VERSION 5.8 ;
BUSBITCHARS "[]" ;
DIVIDERCHAR "/" ;
UNITS
    DATABASE MICRONS 1000 ;
END UNITS

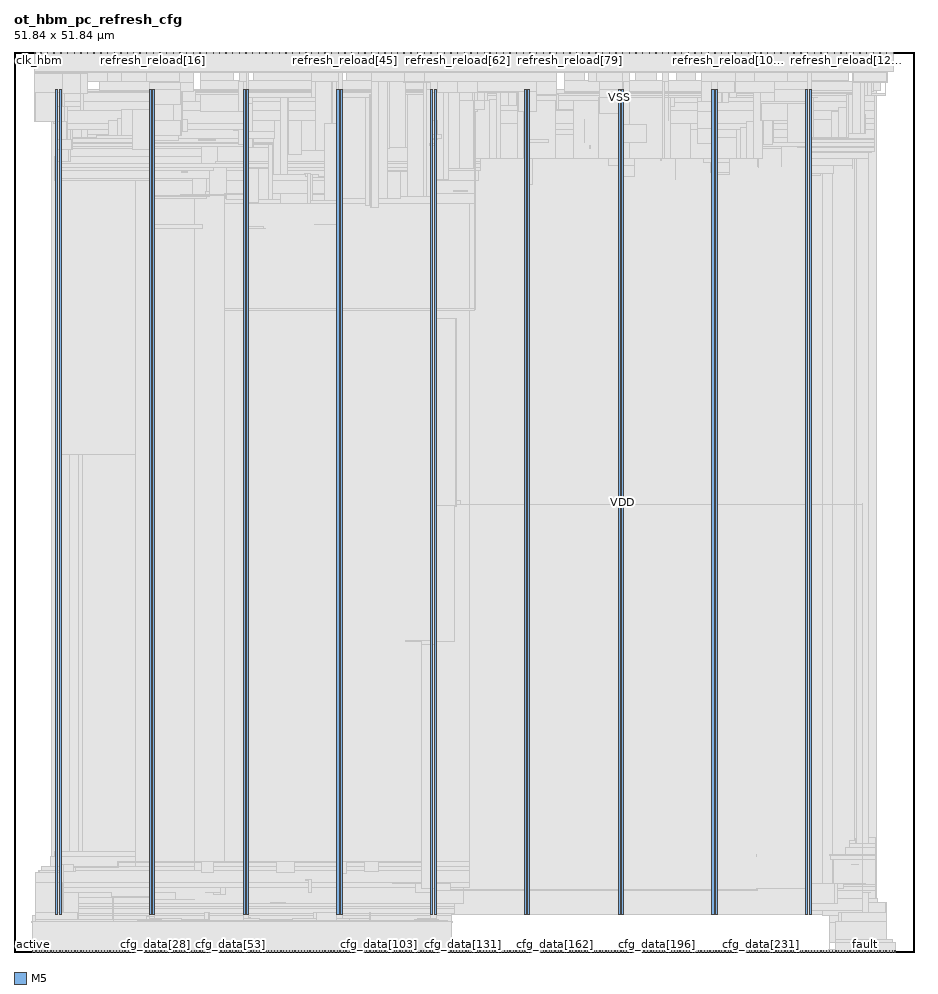
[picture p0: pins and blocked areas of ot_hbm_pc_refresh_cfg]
MACRO ot_hbm_pc_refresh_cfg
  FOREIGN ot_hbm_pc_refresh_cfg 0 0 ;
  CLASS BLOCK ;
  SIZE 51.84 BY 51.84 ;
  PIN active
    DIRECTION OUTPUT ;
    USE SIGNAL ;
    PORT
      LAYER M5 ;
        RECT  1.056 0 1.08 0.084 ;
    END
  END active
  PIN cfg_addr[0]
    DIRECTION INPUT ;
    USE SIGNAL ;
    PORT
      LAYER M5 ;
        RECT  1.248 0 1.272 0.084 ;
    END
  END cfg_addr[0]
  PIN cfg_addr[10]
    DIRECTION INPUT ;
    USE SIGNAL ;
    PORT
      LAYER M5 ;
        RECT  2.976 0 3 0.084 ;
    END
  END cfg_addr[10]
  PIN cfg_addr[11]
    DIRECTION INPUT ;
    USE SIGNAL ;
    PORT
      LAYER M5 ;
        RECT  3.12 0 3.144 0.084 ;
    END
  END cfg_addr[11]
  PIN cfg_addr[1]
    DIRECTION INPUT ;
    USE SIGNAL ;
    PORT
      LAYER M5 ;
        RECT  1.44 0 1.464 0.084 ;
    END
  END cfg_addr[1]
  PIN cfg_addr[2]
    DIRECTION INPUT ;
    USE SIGNAL ;
    PORT
      LAYER M5 ;
        RECT  1.584 0 1.608 0.084 ;
    END
  END cfg_addr[2]
  PIN cfg_addr[3]
    DIRECTION INPUT ;
    USE SIGNAL ;
    PORT
      LAYER M5 ;
        RECT  1.776 0 1.8 0.084 ;
    END
  END cfg_addr[3]
  PIN cfg_addr[4]
    DIRECTION INPUT ;
    USE SIGNAL ;
    PORT
      LAYER M5 ;
        RECT  1.92 0 1.944 0.084 ;
    END
  END cfg_addr[4]
  PIN cfg_addr[5]
    DIRECTION INPUT ;
    USE SIGNAL ;
    PORT
      LAYER M5 ;
        RECT  2.112 0 2.136 0.084 ;
    END
  END cfg_addr[5]
  PIN cfg_addr[6]
    DIRECTION INPUT ;
    USE SIGNAL ;
    PORT
      LAYER M5 ;
        RECT  2.256 0 2.28 0.084 ;
    END
  END cfg_addr[6]
  PIN cfg_addr[7]
    DIRECTION INPUT ;
    USE SIGNAL ;
    PORT
      LAYER M5 ;
        RECT  2.448 0 2.472 0.084 ;
    END
  END cfg_addr[7]
  PIN cfg_addr[8]
    DIRECTION INPUT ;
    USE SIGNAL ;
    PORT
      LAYER M5 ;
        RECT  2.64 0 2.664 0.084 ;
    END
  END cfg_addr[8]
  PIN cfg_addr[9]
    DIRECTION INPUT ;
    USE SIGNAL ;
    PORT
      LAYER M5 ;
        RECT  2.784 0 2.808 0.084 ;
    END
  END cfg_addr[9]
  PIN cfg_data[0]
    DIRECTION INPUT ;
    USE SIGNAL ;
    PORT
      LAYER M5 ;
        RECT  3.312 0 3.336 0.084 ;
    END
  END cfg_data[0]
  PIN cfg_data[100]
    DIRECTION INPUT ;
    USE SIGNAL ;
    PORT
      LAYER M5 ;
        RECT  20.496 0 20.52 0.084 ;
    END
  END cfg_data[100]
  PIN cfg_data[101]
    DIRECTION INPUT ;
    USE SIGNAL ;
    PORT
      LAYER M5 ;
        RECT  20.688 0 20.712 0.084 ;
    END
  END cfg_data[101]
  PIN cfg_data[102]
    DIRECTION INPUT ;
    USE SIGNAL ;
    PORT
      LAYER M5 ;
        RECT  20.832 0 20.856 0.084 ;
    END
  END cfg_data[102]
  PIN cfg_data[103]
    DIRECTION INPUT ;
    USE SIGNAL ;
    PORT
      LAYER M5 ;
        RECT  21.024 0 21.048 0.084 ;
    END
  END cfg_data[103]
  PIN cfg_data[104]
    DIRECTION INPUT ;
    USE SIGNAL ;
    PORT
      LAYER M5 ;
        RECT  21.168 0 21.192 0.084 ;
    END
  END cfg_data[104]
  PIN cfg_data[105]
    DIRECTION INPUT ;
    USE SIGNAL ;
    PORT
      LAYER M5 ;
        RECT  21.36 0 21.384 0.084 ;
    END
  END cfg_data[105]
  PIN cfg_data[106]
    DIRECTION INPUT ;
    USE SIGNAL ;
    PORT
      LAYER M5 ;
        RECT  21.504 0 21.528 0.084 ;
    END
  END cfg_data[106]
  PIN cfg_data[107]
    DIRECTION INPUT ;
    USE SIGNAL ;
    PORT
      LAYER M5 ;
        RECT  21.696 0 21.72 0.084 ;
    END
  END cfg_data[107]
  PIN cfg_data[108]
    DIRECTION INPUT ;
    USE SIGNAL ;
    PORT
      LAYER M5 ;
        RECT  21.888 0 21.912 0.084 ;
    END
  END cfg_data[108]
  PIN cfg_data[109]
    DIRECTION INPUT ;
    USE SIGNAL ;
    PORT
      LAYER M5 ;
        RECT  22.032 0 22.056 0.084 ;
    END
  END cfg_data[109]
  PIN cfg_data[10]
    DIRECTION INPUT ;
    USE SIGNAL ;
    PORT
      LAYER M5 ;
        RECT  5.04 0 5.064 0.084 ;
    END
  END cfg_data[10]
  PIN cfg_data[110]
    DIRECTION INPUT ;
    USE SIGNAL ;
    PORT
      LAYER M5 ;
        RECT  22.224 0 22.248 0.084 ;
    END
  END cfg_data[110]
  PIN cfg_data[111]
    DIRECTION INPUT ;
    USE SIGNAL ;
    PORT
      LAYER M5 ;
        RECT  22.368 0 22.392 0.084 ;
    END
  END cfg_data[111]
  PIN cfg_data[112]
    DIRECTION INPUT ;
    USE SIGNAL ;
    PORT
      LAYER M5 ;
        RECT  22.56 0 22.584 0.084 ;
    END
  END cfg_data[112]
  PIN cfg_data[113]
    DIRECTION INPUT ;
    USE SIGNAL ;
    PORT
      LAYER M5 ;
        RECT  22.752 0 22.776 0.084 ;
    END
  END cfg_data[113]
  PIN cfg_data[114]
    DIRECTION INPUT ;
    USE SIGNAL ;
    PORT
      LAYER M5 ;
        RECT  22.896 0 22.92 0.084 ;
    END
  END cfg_data[114]
  PIN cfg_data[115]
    DIRECTION INPUT ;
    USE SIGNAL ;
    PORT
      LAYER M5 ;
        RECT  23.088 0 23.112 0.084 ;
    END
  END cfg_data[115]
  PIN cfg_data[116]
    DIRECTION INPUT ;
    USE SIGNAL ;
    PORT
      LAYER M5 ;
        RECT  23.232 0 23.256 0.084 ;
    END
  END cfg_data[116]
  PIN cfg_data[117]
    DIRECTION INPUT ;
    USE SIGNAL ;
    PORT
      LAYER M5 ;
        RECT  23.424 0 23.448 0.084 ;
    END
  END cfg_data[117]
  PIN cfg_data[118]
    DIRECTION INPUT ;
    USE SIGNAL ;
    PORT
      LAYER M5 ;
        RECT  23.568 0 23.592 0.084 ;
    END
  END cfg_data[118]
  PIN cfg_data[119]
    DIRECTION INPUT ;
    USE SIGNAL ;
    PORT
      LAYER M5 ;
        RECT  23.76 0 23.784 0.084 ;
    END
  END cfg_data[119]
  PIN cfg_data[11]
    DIRECTION INPUT ;
    USE SIGNAL ;
    PORT
      LAYER M5 ;
        RECT  5.184 0 5.208 0.084 ;
    END
  END cfg_data[11]
  PIN cfg_data[120]
    DIRECTION INPUT ;
    USE SIGNAL ;
    PORT
      LAYER M5 ;
        RECT  23.952 0 23.976 0.084 ;
    END
  END cfg_data[120]
  PIN cfg_data[121]
    DIRECTION INPUT ;
    USE SIGNAL ;
    PORT
      LAYER M5 ;
        RECT  24.096 0 24.12 0.084 ;
    END
  END cfg_data[121]
  PIN cfg_data[122]
    DIRECTION INPUT ;
    USE SIGNAL ;
    PORT
      LAYER M5 ;
        RECT  24.288 0 24.312 0.084 ;
    END
  END cfg_data[122]
  PIN cfg_data[123]
    DIRECTION INPUT ;
    USE SIGNAL ;
    PORT
      LAYER M5 ;
        RECT  24.432 0 24.456 0.084 ;
    END
  END cfg_data[123]
  PIN cfg_data[124]
    DIRECTION INPUT ;
    USE SIGNAL ;
    PORT
      LAYER M5 ;
        RECT  24.624 0 24.648 0.084 ;
    END
  END cfg_data[124]
  PIN cfg_data[125]
    DIRECTION INPUT ;
    USE SIGNAL ;
    PORT
      LAYER M5 ;
        RECT  24.768 0 24.792 0.084 ;
    END
  END cfg_data[125]
  PIN cfg_data[126]
    DIRECTION INPUT ;
    USE SIGNAL ;
    PORT
      LAYER M5 ;
        RECT  24.96 0 24.984 0.084 ;
    END
  END cfg_data[126]
  PIN cfg_data[127]
    DIRECTION INPUT ;
    USE SIGNAL ;
    PORT
      LAYER M5 ;
        RECT  25.152 0 25.176 0.084 ;
    END
  END cfg_data[127]
  PIN cfg_data[128]
    DIRECTION INPUT ;
    USE SIGNAL ;
    PORT
      LAYER M5 ;
        RECT  25.296 0 25.32 0.084 ;
    END
  END cfg_data[128]
  PIN cfg_data[129]
    DIRECTION INPUT ;
    USE SIGNAL ;
    PORT
      LAYER M5 ;
        RECT  25.488 0 25.512 0.084 ;
    END
  END cfg_data[129]
  PIN cfg_data[12]
    DIRECTION INPUT ;
    USE SIGNAL ;
    PORT
      LAYER M5 ;
        RECT  5.376 0 5.4 0.084 ;
    END
  END cfg_data[12]
  PIN cfg_data[130]
    DIRECTION INPUT ;
    USE SIGNAL ;
    PORT
      LAYER M5 ;
        RECT  25.632 0 25.656 0.084 ;
    END
  END cfg_data[130]
  PIN cfg_data[131]
    DIRECTION INPUT ;
    USE SIGNAL ;
    PORT
      LAYER M5 ;
        RECT  25.824 0 25.848 0.084 ;
    END
  END cfg_data[131]
  PIN cfg_data[132]
    DIRECTION INPUT ;
    USE SIGNAL ;
    PORT
      LAYER M5 ;
        RECT  26.016 0 26.04 0.084 ;
    END
  END cfg_data[132]
  PIN cfg_data[133]
    DIRECTION INPUT ;
    USE SIGNAL ;
    PORT
      LAYER M5 ;
        RECT  26.16 0 26.184 0.084 ;
    END
  END cfg_data[133]
  PIN cfg_data[134]
    DIRECTION INPUT ;
    USE SIGNAL ;
    PORT
      LAYER M5 ;
        RECT  26.352 0 26.376 0.084 ;
    END
  END cfg_data[134]
  PIN cfg_data[135]
    DIRECTION INPUT ;
    USE SIGNAL ;
    PORT
      LAYER M5 ;
        RECT  26.496 0 26.52 0.084 ;
    END
  END cfg_data[135]
  PIN cfg_data[136]
    DIRECTION INPUT ;
    USE SIGNAL ;
    PORT
      LAYER M5 ;
        RECT  26.688 0 26.712 0.084 ;
    END
  END cfg_data[136]
  PIN cfg_data[137]
    DIRECTION INPUT ;
    USE SIGNAL ;
    PORT
      LAYER M5 ;
        RECT  26.832 0 26.856 0.084 ;
    END
  END cfg_data[137]
  PIN cfg_data[138]
    DIRECTION INPUT ;
    USE SIGNAL ;
    PORT
      LAYER M5 ;
        RECT  27.024 0 27.048 0.084 ;
    END
  END cfg_data[138]
  PIN cfg_data[139]
    DIRECTION INPUT ;
    USE SIGNAL ;
    PORT
      LAYER M5 ;
        RECT  27.216 0 27.24 0.084 ;
    END
  END cfg_data[139]
  PIN cfg_data[13]
    DIRECTION INPUT ;
    USE SIGNAL ;
    PORT
      LAYER M5 ;
        RECT  5.52 0 5.544 0.084 ;
    END
  END cfg_data[13]
  PIN cfg_data[140]
    DIRECTION INPUT ;
    USE SIGNAL ;
    PORT
      LAYER M5 ;
        RECT  27.36 0 27.384 0.084 ;
    END
  END cfg_data[140]
  PIN cfg_data[141]
    DIRECTION INPUT ;
    USE SIGNAL ;
    PORT
      LAYER M5 ;
        RECT  27.552 0 27.576 0.084 ;
    END
  END cfg_data[141]
  PIN cfg_data[142]
    DIRECTION INPUT ;
    USE SIGNAL ;
    PORT
      LAYER M5 ;
        RECT  27.696 0 27.72 0.084 ;
    END
  END cfg_data[142]
  PIN cfg_data[143]
    DIRECTION INPUT ;
    USE SIGNAL ;
    PORT
      LAYER M5 ;
        RECT  27.888 0 27.912 0.084 ;
    END
  END cfg_data[143]
  PIN cfg_data[144]
    DIRECTION INPUT ;
    USE SIGNAL ;
    PORT
      LAYER M5 ;
        RECT  28.08 0 28.104 0.084 ;
    END
  END cfg_data[144]
  PIN cfg_data[145]
    DIRECTION INPUT ;
    USE SIGNAL ;
    PORT
      LAYER M5 ;
        RECT  28.224 0 28.248 0.084 ;
    END
  END cfg_data[145]
  PIN cfg_data[146]
    DIRECTION INPUT ;
    USE SIGNAL ;
    PORT
      LAYER M5 ;
        RECT  28.416 0 28.44 0.084 ;
    END
  END cfg_data[146]
  PIN cfg_data[147]
    DIRECTION INPUT ;
    USE SIGNAL ;
    PORT
      LAYER M5 ;
        RECT  28.56 0 28.584 0.084 ;
    END
  END cfg_data[147]
  PIN cfg_data[148]
    DIRECTION INPUT ;
    USE SIGNAL ;
    PORT
      LAYER M5 ;
        RECT  28.752 0 28.776 0.084 ;
    END
  END cfg_data[148]
  PIN cfg_data[149]
    DIRECTION INPUT ;
    USE SIGNAL ;
    PORT
      LAYER M5 ;
        RECT  28.896 0 28.92 0.084 ;
    END
  END cfg_data[149]
  PIN cfg_data[14]
    DIRECTION INPUT ;
    USE SIGNAL ;
    PORT
      LAYER M5 ;
        RECT  5.712 0 5.736 0.084 ;
    END
  END cfg_data[14]
  PIN cfg_data[150]
    DIRECTION INPUT ;
    USE SIGNAL ;
    PORT
      LAYER M5 ;
        RECT  29.088 0 29.112 0.084 ;
    END
  END cfg_data[150]
  PIN cfg_data[151]
    DIRECTION INPUT ;
    USE SIGNAL ;
    PORT
      LAYER M5 ;
        RECT  29.28 0 29.304 0.084 ;
    END
  END cfg_data[151]
  PIN cfg_data[152]
    DIRECTION INPUT ;
    USE SIGNAL ;
    PORT
      LAYER M5 ;
        RECT  29.424 0 29.448 0.084 ;
    END
  END cfg_data[152]
  PIN cfg_data[153]
    DIRECTION INPUT ;
    USE SIGNAL ;
    PORT
      LAYER M5 ;
        RECT  29.616 0 29.64 0.084 ;
    END
  END cfg_data[153]
  PIN cfg_data[154]
    DIRECTION INPUT ;
    USE SIGNAL ;
    PORT
      LAYER M5 ;
        RECT  29.76 0 29.784 0.084 ;
    END
  END cfg_data[154]
  PIN cfg_data[155]
    DIRECTION INPUT ;
    USE SIGNAL ;
    PORT
      LAYER M5 ;
        RECT  29.952 0 29.976 0.084 ;
    END
  END cfg_data[155]
  PIN cfg_data[156]
    DIRECTION INPUT ;
    USE SIGNAL ;
    PORT
      LAYER M5 ;
        RECT  30.096 0 30.12 0.084 ;
    END
  END cfg_data[156]
  PIN cfg_data[157]
    DIRECTION INPUT ;
    USE SIGNAL ;
    PORT
      LAYER M5 ;
        RECT  30.288 0 30.312 0.084 ;
    END
  END cfg_data[157]
  PIN cfg_data[158]
    DIRECTION INPUT ;
    USE SIGNAL ;
    PORT
      LAYER M5 ;
        RECT  30.48 0 30.504 0.084 ;
    END
  END cfg_data[158]
  PIN cfg_data[159]
    DIRECTION INPUT ;
    USE SIGNAL ;
    PORT
      LAYER M5 ;
        RECT  30.624 0 30.648 0.084 ;
    END
  END cfg_data[159]
  PIN cfg_data[15]
    DIRECTION INPUT ;
    USE SIGNAL ;
    PORT
      LAYER M5 ;
        RECT  5.904 0 5.928 0.084 ;
    END
  END cfg_data[15]
  PIN cfg_data[160]
    DIRECTION INPUT ;
    USE SIGNAL ;
    PORT
      LAYER M5 ;
        RECT  30.816 0 30.84 0.084 ;
    END
  END cfg_data[160]
  PIN cfg_data[161]
    DIRECTION INPUT ;
    USE SIGNAL ;
    PORT
      LAYER M5 ;
        RECT  30.96 0 30.984 0.084 ;
    END
  END cfg_data[161]
  PIN cfg_data[162]
    DIRECTION INPUT ;
    USE SIGNAL ;
    PORT
      LAYER M5 ;
        RECT  31.152 0 31.176 0.084 ;
    END
  END cfg_data[162]
  PIN cfg_data[163]
    DIRECTION INPUT ;
    USE SIGNAL ;
    PORT
      LAYER M5 ;
        RECT  31.344 0 31.368 0.084 ;
    END
  END cfg_data[163]
  PIN cfg_data[164]
    DIRECTION INPUT ;
    USE SIGNAL ;
    PORT
      LAYER M5 ;
        RECT  31.488 0 31.512 0.084 ;
    END
  END cfg_data[164]
  PIN cfg_data[165]
    DIRECTION INPUT ;
    USE SIGNAL ;
    PORT
      LAYER M5 ;
        RECT  31.68 0 31.704 0.084 ;
    END
  END cfg_data[165]
  PIN cfg_data[166]
    DIRECTION INPUT ;
    USE SIGNAL ;
    PORT
      LAYER M5 ;
        RECT  31.824 0 31.848 0.084 ;
    END
  END cfg_data[166]
  PIN cfg_data[167]
    DIRECTION INPUT ;
    USE SIGNAL ;
    PORT
      LAYER M5 ;
        RECT  32.016 0 32.04 0.084 ;
    END
  END cfg_data[167]
  PIN cfg_data[168]
    DIRECTION INPUT ;
    USE SIGNAL ;
    PORT
      LAYER M5 ;
        RECT  32.16 0 32.184 0.084 ;
    END
  END cfg_data[168]
  PIN cfg_data[169]
    DIRECTION INPUT ;
    USE SIGNAL ;
    PORT
      LAYER M5 ;
        RECT  32.352 0 32.376 0.084 ;
    END
  END cfg_data[169]
  PIN cfg_data[16]
    DIRECTION INPUT ;
    USE SIGNAL ;
    PORT
      LAYER M5 ;
        RECT  6.048 0 6.072 0.084 ;
    END
  END cfg_data[16]
  PIN cfg_data[170]
    DIRECTION INPUT ;
    USE SIGNAL ;
    PORT
      LAYER M5 ;
        RECT  32.544 0 32.568 0.084 ;
    END
  END cfg_data[170]
  PIN cfg_data[171]
    DIRECTION INPUT ;
    USE SIGNAL ;
    PORT
      LAYER M5 ;
        RECT  32.688 0 32.712 0.084 ;
    END
  END cfg_data[171]
  PIN cfg_data[172]
    DIRECTION INPUT ;
    USE SIGNAL ;
    PORT
      LAYER M5 ;
        RECT  32.88 0 32.904 0.084 ;
    END
  END cfg_data[172]
  PIN cfg_data[173]
    DIRECTION INPUT ;
    USE SIGNAL ;
    PORT
      LAYER M5 ;
        RECT  33.024 0 33.048 0.084 ;
    END
  END cfg_data[173]
  PIN cfg_data[174]
    DIRECTION INPUT ;
    USE SIGNAL ;
    PORT
      LAYER M5 ;
        RECT  33.216 0 33.24 0.084 ;
    END
  END cfg_data[174]
  PIN cfg_data[175]
    DIRECTION INPUT ;
    USE SIGNAL ;
    PORT
      LAYER M5 ;
        RECT  33.408 0 33.432 0.084 ;
    END
  END cfg_data[175]
  PIN cfg_data[176]
    DIRECTION INPUT ;
    USE SIGNAL ;
    PORT
      LAYER M5 ;
        RECT  33.552 0 33.576 0.084 ;
    END
  END cfg_data[176]
  PIN cfg_data[177]
    DIRECTION INPUT ;
    USE SIGNAL ;
    PORT
      LAYER M5 ;
        RECT  33.744 0 33.768 0.084 ;
    END
  END cfg_data[177]
  PIN cfg_data[178]
    DIRECTION INPUT ;
    USE SIGNAL ;
    PORT
      LAYER M5 ;
        RECT  33.888 0 33.912 0.084 ;
    END
  END cfg_data[178]
  PIN cfg_data[179]
    DIRECTION INPUT ;
    USE SIGNAL ;
    PORT
      LAYER M5 ;
        RECT  34.08 0 34.104 0.084 ;
    END
  END cfg_data[179]
  PIN cfg_data[17]
    DIRECTION INPUT ;
    USE SIGNAL ;
    PORT
      LAYER M5 ;
        RECT  6.24 0 6.264 0.084 ;
    END
  END cfg_data[17]
  PIN cfg_data[180]
    DIRECTION INPUT ;
    USE SIGNAL ;
    PORT
      LAYER M5 ;
        RECT  34.224 0 34.248 0.084 ;
    END
  END cfg_data[180]
  PIN cfg_data[181]
    DIRECTION INPUT ;
    USE SIGNAL ;
    PORT
      LAYER M5 ;
        RECT  34.416 0 34.44 0.084 ;
    END
  END cfg_data[181]
  PIN cfg_data[182]
    DIRECTION INPUT ;
    USE SIGNAL ;
    PORT
      LAYER M5 ;
        RECT  34.608 0 34.632 0.084 ;
    END
  END cfg_data[182]
  PIN cfg_data[183]
    DIRECTION INPUT ;
    USE SIGNAL ;
    PORT
      LAYER M5 ;
        RECT  34.752 0 34.776 0.084 ;
    END
  END cfg_data[183]
  PIN cfg_data[184]
    DIRECTION INPUT ;
    USE SIGNAL ;
    PORT
      LAYER M5 ;
        RECT  34.944 0 34.968 0.084 ;
    END
  END cfg_data[184]
  PIN cfg_data[185]
    DIRECTION INPUT ;
    USE SIGNAL ;
    PORT
      LAYER M5 ;
        RECT  35.088 0 35.112 0.084 ;
    END
  END cfg_data[185]
  PIN cfg_data[186]
    DIRECTION INPUT ;
    USE SIGNAL ;
    PORT
      LAYER M5 ;
        RECT  35.28 0 35.304 0.084 ;
    END
  END cfg_data[186]
  PIN cfg_data[187]
    DIRECTION INPUT ;
    USE SIGNAL ;
    PORT
      LAYER M5 ;
        RECT  35.424 0 35.448 0.084 ;
    END
  END cfg_data[187]
  PIN cfg_data[188]
    DIRECTION INPUT ;
    USE SIGNAL ;
    PORT
      LAYER M5 ;
        RECT  35.616 0 35.64 0.084 ;
    END
  END cfg_data[188]
  PIN cfg_data[189]
    DIRECTION INPUT ;
    USE SIGNAL ;
    PORT
      LAYER M5 ;
        RECT  35.808 0 35.832 0.084 ;
    END
  END cfg_data[189]
  PIN cfg_data[18]
    DIRECTION INPUT ;
    USE SIGNAL ;
    PORT
      LAYER M5 ;
        RECT  6.384 0 6.408 0.084 ;
    END
  END cfg_data[18]
  PIN cfg_data[190]
    DIRECTION INPUT ;
    USE SIGNAL ;
    PORT
      LAYER M5 ;
        RECT  35.952 0 35.976 0.084 ;
    END
  END cfg_data[190]
  PIN cfg_data[191]
    DIRECTION INPUT ;
    USE SIGNAL ;
    PORT
      LAYER M5 ;
        RECT  36.144 0 36.168 0.084 ;
    END
  END cfg_data[191]
  PIN cfg_data[192]
    DIRECTION INPUT ;
    USE SIGNAL ;
    PORT
      LAYER M5 ;
        RECT  36.288 0 36.312 0.084 ;
    END
  END cfg_data[192]
  PIN cfg_data[193]
    DIRECTION INPUT ;
    USE SIGNAL ;
    PORT
      LAYER M5 ;
        RECT  36.48 0 36.504 0.084 ;
    END
  END cfg_data[193]
  PIN cfg_data[194]
    DIRECTION INPUT ;
    USE SIGNAL ;
    PORT
      LAYER M5 ;
        RECT  36.672 0 36.696 0.084 ;
    END
  END cfg_data[194]
  PIN cfg_data[195]
    DIRECTION INPUT ;
    USE SIGNAL ;
    PORT
      LAYER M5 ;
        RECT  36.816 0 36.84 0.084 ;
    END
  END cfg_data[195]
  PIN cfg_data[196]
    DIRECTION INPUT ;
    USE SIGNAL ;
    PORT
      LAYER M5 ;
        RECT  37.008 0 37.032 0.084 ;
    END
  END cfg_data[196]
  PIN cfg_data[197]
    DIRECTION INPUT ;
    USE SIGNAL ;
    PORT
      LAYER M5 ;
        RECT  37.152 0 37.176 0.084 ;
    END
  END cfg_data[197]
  PIN cfg_data[198]
    DIRECTION INPUT ;
    USE SIGNAL ;
    PORT
      LAYER M5 ;
        RECT  37.344 0 37.368 0.084 ;
    END
  END cfg_data[198]
  PIN cfg_data[199]
    DIRECTION INPUT ;
    USE SIGNAL ;
    PORT
      LAYER M5 ;
        RECT  37.488 0 37.512 0.084 ;
    END
  END cfg_data[199]
  PIN cfg_data[19]
    DIRECTION INPUT ;
    USE SIGNAL ;
    PORT
      LAYER M5 ;
        RECT  6.576 0 6.6 0.084 ;
    END
  END cfg_data[19]
  PIN cfg_data[1]
    DIRECTION INPUT ;
    USE SIGNAL ;
    PORT
      LAYER M5 ;
        RECT  3.504 0 3.528 0.084 ;
    END
  END cfg_data[1]
  PIN cfg_data[200]
    DIRECTION INPUT ;
    USE SIGNAL ;
    PORT
      LAYER M5 ;
        RECT  37.68 0 37.704 0.084 ;
    END
  END cfg_data[200]
  PIN cfg_data[201]
    DIRECTION INPUT ;
    USE SIGNAL ;
    PORT
      LAYER M5 ;
        RECT  37.872 0 37.896 0.084 ;
    END
  END cfg_data[201]
  PIN cfg_data[202]
    DIRECTION INPUT ;
    USE SIGNAL ;
    PORT
      LAYER M5 ;
        RECT  38.016 0 38.04 0.084 ;
    END
  END cfg_data[202]
  PIN cfg_data[203]
    DIRECTION INPUT ;
    USE SIGNAL ;
    PORT
      LAYER M5 ;
        RECT  38.208 0 38.232 0.084 ;
    END
  END cfg_data[203]
  PIN cfg_data[204]
    DIRECTION INPUT ;
    USE SIGNAL ;
    PORT
      LAYER M5 ;
        RECT  38.352 0 38.376 0.084 ;
    END
  END cfg_data[204]
  PIN cfg_data[205]
    DIRECTION INPUT ;
    USE SIGNAL ;
    PORT
      LAYER M5 ;
        RECT  38.544 0 38.568 0.084 ;
    END
  END cfg_data[205]
  PIN cfg_data[206]
    DIRECTION INPUT ;
    USE SIGNAL ;
    PORT
      LAYER M5 ;
        RECT  38.736 0 38.76 0.084 ;
    END
  END cfg_data[206]
  PIN cfg_data[207]
    DIRECTION INPUT ;
    USE SIGNAL ;
    PORT
      LAYER M5 ;
        RECT  38.88 0 38.904 0.084 ;
    END
  END cfg_data[207]
  PIN cfg_data[208]
    DIRECTION INPUT ;
    USE SIGNAL ;
    PORT
      LAYER M5 ;
        RECT  39.072 0 39.096 0.084 ;
    END
  END cfg_data[208]
  PIN cfg_data[209]
    DIRECTION INPUT ;
    USE SIGNAL ;
    PORT
      LAYER M5 ;
        RECT  39.216 0 39.24 0.084 ;
    END
  END cfg_data[209]
  PIN cfg_data[20]
    DIRECTION INPUT ;
    USE SIGNAL ;
    PORT
      LAYER M5 ;
        RECT  6.768 0 6.792 0.084 ;
    END
  END cfg_data[20]
  PIN cfg_data[210]
    DIRECTION INPUT ;
    USE SIGNAL ;
    PORT
      LAYER M5 ;
        RECT  39.408 0 39.432 0.084 ;
    END
  END cfg_data[210]
  PIN cfg_data[211]
    DIRECTION INPUT ;
    USE SIGNAL ;
    PORT
      LAYER M5 ;
        RECT  39.552 0 39.576 0.084 ;
    END
  END cfg_data[211]
  PIN cfg_data[212]
    DIRECTION INPUT ;
    USE SIGNAL ;
    PORT
      LAYER M5 ;
        RECT  39.744 0 39.768 0.084 ;
    END
  END cfg_data[212]
  PIN cfg_data[213]
    DIRECTION INPUT ;
    USE SIGNAL ;
    PORT
      LAYER M5 ;
        RECT  39.936 0 39.96 0.084 ;
    END
  END cfg_data[213]
  PIN cfg_data[214]
    DIRECTION INPUT ;
    USE SIGNAL ;
    PORT
      LAYER M5 ;
        RECT  40.08 0 40.104 0.084 ;
    END
  END cfg_data[214]
  PIN cfg_data[215]
    DIRECTION INPUT ;
    USE SIGNAL ;
    PORT
      LAYER M5 ;
        RECT  40.272 0 40.296 0.084 ;
    END
  END cfg_data[215]
  PIN cfg_data[216]
    DIRECTION INPUT ;
    USE SIGNAL ;
    PORT
      LAYER M5 ;
        RECT  40.416 0 40.44 0.084 ;
    END
  END cfg_data[216]
  PIN cfg_data[217]
    DIRECTION INPUT ;
    USE SIGNAL ;
    PORT
      LAYER M5 ;
        RECT  40.608 0 40.632 0.084 ;
    END
  END cfg_data[217]
  PIN cfg_data[218]
    DIRECTION INPUT ;
    USE SIGNAL ;
    PORT
      LAYER M5 ;
        RECT  40.752 0 40.776 0.084 ;
    END
  END cfg_data[218]
  PIN cfg_data[219]
    DIRECTION INPUT ;
    USE SIGNAL ;
    PORT
      LAYER M5 ;
        RECT  40.944 0 40.968 0.084 ;
    END
  END cfg_data[219]
  PIN cfg_data[21]
    DIRECTION INPUT ;
    USE SIGNAL ;
    PORT
      LAYER M5 ;
        RECT  6.912 0 6.936 0.084 ;
    END
  END cfg_data[21]
  PIN cfg_data[220]
    DIRECTION INPUT ;
    USE SIGNAL ;
    PORT
      LAYER M5 ;
        RECT  41.136 0 41.16 0.084 ;
    END
  END cfg_data[220]
  PIN cfg_data[221]
    DIRECTION INPUT ;
    USE SIGNAL ;
    PORT
      LAYER M5 ;
        RECT  41.28 0 41.304 0.084 ;
    END
  END cfg_data[221]
  PIN cfg_data[222]
    DIRECTION INPUT ;
    USE SIGNAL ;
    PORT
      LAYER M5 ;
        RECT  41.472 0 41.496 0.084 ;
    END
  END cfg_data[222]
  PIN cfg_data[223]
    DIRECTION INPUT ;
    USE SIGNAL ;
    PORT
      LAYER M5 ;
        RECT  41.616 0 41.64 0.084 ;
    END
  END cfg_data[223]
  PIN cfg_data[224]
    DIRECTION INPUT ;
    USE SIGNAL ;
    PORT
      LAYER M5 ;
        RECT  41.808 0 41.832 0.084 ;
    END
  END cfg_data[224]
  PIN cfg_data[225]
    DIRECTION INPUT ;
    USE SIGNAL ;
    PORT
      LAYER M5 ;
        RECT  42 0 42.024 0.084 ;
    END
  END cfg_data[225]
  PIN cfg_data[226]
    DIRECTION INPUT ;
    USE SIGNAL ;
    PORT
      LAYER M5 ;
        RECT  42.144 0 42.168 0.084 ;
    END
  END cfg_data[226]
  PIN cfg_data[227]
    DIRECTION INPUT ;
    USE SIGNAL ;
    PORT
      LAYER M5 ;
        RECT  42.336 0 42.36 0.084 ;
    END
  END cfg_data[227]
  PIN cfg_data[228]
    DIRECTION INPUT ;
    USE SIGNAL ;
    PORT
      LAYER M5 ;
        RECT  42.48 0 42.504 0.084 ;
    END
  END cfg_data[228]
  PIN cfg_data[229]
    DIRECTION INPUT ;
    USE SIGNAL ;
    PORT
      LAYER M5 ;
        RECT  42.672 0 42.696 0.084 ;
    END
  END cfg_data[229]
  PIN cfg_data[22]
    DIRECTION INPUT ;
    USE SIGNAL ;
    PORT
      LAYER M5 ;
        RECT  7.104 0 7.128 0.084 ;
    END
  END cfg_data[22]
  PIN cfg_data[230]
    DIRECTION INPUT ;
    USE SIGNAL ;
    PORT
      LAYER M5 ;
        RECT  42.816 0 42.84 0.084 ;
    END
  END cfg_data[230]
  PIN cfg_data[231]
    DIRECTION INPUT ;
    USE SIGNAL ;
    PORT
      LAYER M5 ;
        RECT  43.008 0 43.032 0.084 ;
    END
  END cfg_data[231]
  PIN cfg_data[232]
    DIRECTION INPUT ;
    USE SIGNAL ;
    PORT
      LAYER M5 ;
        RECT  43.2 0 43.224 0.084 ;
    END
  END cfg_data[232]
  PIN cfg_data[233]
    DIRECTION INPUT ;
    USE SIGNAL ;
    PORT
      LAYER M5 ;
        RECT  43.344 0 43.368 0.084 ;
    END
  END cfg_data[233]
  PIN cfg_data[234]
    DIRECTION INPUT ;
    USE SIGNAL ;
    PORT
      LAYER M5 ;
        RECT  43.536 0 43.56 0.084 ;
    END
  END cfg_data[234]
  PIN cfg_data[235]
    DIRECTION INPUT ;
    USE SIGNAL ;
    PORT
      LAYER M5 ;
        RECT  43.68 0 43.704 0.084 ;
    END
  END cfg_data[235]
  PIN cfg_data[236]
    DIRECTION INPUT ;
    USE SIGNAL ;
    PORT
      LAYER M5 ;
        RECT  43.872 0 43.896 0.084 ;
    END
  END cfg_data[236]
  PIN cfg_data[237]
    DIRECTION INPUT ;
    USE SIGNAL ;
    PORT
      LAYER M5 ;
        RECT  44.016 0 44.04 0.084 ;
    END
  END cfg_data[237]
  PIN cfg_data[238]
    DIRECTION INPUT ;
    USE SIGNAL ;
    PORT
      LAYER M5 ;
        RECT  44.208 0 44.232 0.084 ;
    END
  END cfg_data[238]
  PIN cfg_data[239]
    DIRECTION INPUT ;
    USE SIGNAL ;
    PORT
      LAYER M5 ;
        RECT  44.4 0 44.424 0.084 ;
    END
  END cfg_data[239]
  PIN cfg_data[23]
    DIRECTION INPUT ;
    USE SIGNAL ;
    PORT
      LAYER M5 ;
        RECT  7.248 0 7.272 0.084 ;
    END
  END cfg_data[23]
  PIN cfg_data[240]
    DIRECTION INPUT ;
    USE SIGNAL ;
    PORT
      LAYER M5 ;
        RECT  44.544 0 44.568 0.084 ;
    END
  END cfg_data[240]
  PIN cfg_data[241]
    DIRECTION INPUT ;
    USE SIGNAL ;
    PORT
      LAYER M5 ;
        RECT  44.736 0 44.76 0.084 ;
    END
  END cfg_data[241]
  PIN cfg_data[242]
    DIRECTION INPUT ;
    USE SIGNAL ;
    PORT
      LAYER M5 ;
        RECT  44.88 0 44.904 0.084 ;
    END
  END cfg_data[242]
  PIN cfg_data[243]
    DIRECTION INPUT ;
    USE SIGNAL ;
    PORT
      LAYER M5 ;
        RECT  45.072 0 45.096 0.084 ;
    END
  END cfg_data[243]
  PIN cfg_data[244]
    DIRECTION INPUT ;
    USE SIGNAL ;
    PORT
      LAYER M5 ;
        RECT  45.264 0 45.288 0.084 ;
    END
  END cfg_data[244]
  PIN cfg_data[245]
    DIRECTION INPUT ;
    USE SIGNAL ;
    PORT
      LAYER M5 ;
        RECT  45.408 0 45.432 0.084 ;
    END
  END cfg_data[245]
  PIN cfg_data[246]
    DIRECTION INPUT ;
    USE SIGNAL ;
    PORT
      LAYER M5 ;
        RECT  45.6 0 45.624 0.084 ;
    END
  END cfg_data[246]
  PIN cfg_data[247]
    DIRECTION INPUT ;
    USE SIGNAL ;
    PORT
      LAYER M5 ;
        RECT  45.744 0 45.768 0.084 ;
    END
  END cfg_data[247]
  PIN cfg_data[248]
    DIRECTION INPUT ;
    USE SIGNAL ;
    PORT
      LAYER M5 ;
        RECT  45.936 0 45.96 0.084 ;
    END
  END cfg_data[248]
  PIN cfg_data[249]
    DIRECTION INPUT ;
    USE SIGNAL ;
    PORT
      LAYER M5 ;
        RECT  46.08 0 46.104 0.084 ;
    END
  END cfg_data[249]
  PIN cfg_data[24]
    DIRECTION INPUT ;
    USE SIGNAL ;
    PORT
      LAYER M5 ;
        RECT  7.44 0 7.464 0.084 ;
    END
  END cfg_data[24]
  PIN cfg_data[250]
    DIRECTION INPUT ;
    USE SIGNAL ;
    PORT
      LAYER M5 ;
        RECT  46.272 0 46.296 0.084 ;
    END
  END cfg_data[250]
  PIN cfg_data[251]
    DIRECTION INPUT ;
    USE SIGNAL ;
    PORT
      LAYER M5 ;
        RECT  46.464 0 46.488 0.084 ;
    END
  END cfg_data[251]
  PIN cfg_data[252]
    DIRECTION INPUT ;
    USE SIGNAL ;
    PORT
      LAYER M5 ;
        RECT  46.608 0 46.632 0.084 ;
    END
  END cfg_data[252]
  PIN cfg_data[253]
    DIRECTION INPUT ;
    USE SIGNAL ;
    PORT
      LAYER M5 ;
        RECT  46.8 0 46.824 0.084 ;
    END
  END cfg_data[253]
  PIN cfg_data[254]
    DIRECTION INPUT ;
    USE SIGNAL ;
    PORT
      LAYER M5 ;
        RECT  46.944 0 46.968 0.084 ;
    END
  END cfg_data[254]
  PIN cfg_data[255]
    DIRECTION INPUT ;
    USE SIGNAL ;
    PORT
      LAYER M5 ;
        RECT  47.136 0 47.16 0.084 ;
    END
  END cfg_data[255]
  PIN cfg_data[25]
    DIRECTION INPUT ;
    USE SIGNAL ;
    PORT
      LAYER M5 ;
        RECT  7.584 0 7.608 0.084 ;
    END
  END cfg_data[25]
  PIN cfg_data[26]
    DIRECTION INPUT ;
    USE SIGNAL ;
    PORT
      LAYER M5 ;
        RECT  7.776 0 7.8 0.084 ;
    END
  END cfg_data[26]
  PIN cfg_data[27]
    DIRECTION INPUT ;
    USE SIGNAL ;
    PORT
      LAYER M5 ;
        RECT  7.968 0 7.992 0.084 ;
    END
  END cfg_data[27]
  PIN cfg_data[28]
    DIRECTION INPUT ;
    USE SIGNAL ;
    PORT
      LAYER M5 ;
        RECT  8.112 0 8.136 0.084 ;
    END
  END cfg_data[28]
  PIN cfg_data[29]
    DIRECTION INPUT ;
    USE SIGNAL ;
    PORT
      LAYER M5 ;
        RECT  8.304 0 8.328 0.084 ;
    END
  END cfg_data[29]
  PIN cfg_data[2]
    DIRECTION INPUT ;
    USE SIGNAL ;
    PORT
      LAYER M5 ;
        RECT  3.648 0 3.672 0.084 ;
    END
  END cfg_data[2]
  PIN cfg_data[30]
    DIRECTION INPUT ;
    USE SIGNAL ;
    PORT
      LAYER M5 ;
        RECT  8.448 0 8.472 0.084 ;
    END
  END cfg_data[30]
  PIN cfg_data[31]
    DIRECTION INPUT ;
    USE SIGNAL ;
    PORT
      LAYER M5 ;
        RECT  8.64 0 8.664 0.084 ;
    END
  END cfg_data[31]
  PIN cfg_data[32]
    DIRECTION INPUT ;
    USE SIGNAL ;
    PORT
      LAYER M5 ;
        RECT  8.832 0 8.856 0.084 ;
    END
  END cfg_data[32]
  PIN cfg_data[33]
    DIRECTION INPUT ;
    USE SIGNAL ;
    PORT
      LAYER M5 ;
        RECT  8.976 0 9 0.084 ;
    END
  END cfg_data[33]
  PIN cfg_data[34]
    DIRECTION INPUT ;
    USE SIGNAL ;
    PORT
      LAYER M5 ;
        RECT  9.168 0 9.192 0.084 ;
    END
  END cfg_data[34]
  PIN cfg_data[35]
    DIRECTION INPUT ;
    USE SIGNAL ;
    PORT
      LAYER M5 ;
        RECT  9.312 0 9.336 0.084 ;
    END
  END cfg_data[35]
  PIN cfg_data[36]
    DIRECTION INPUT ;
    USE SIGNAL ;
    PORT
      LAYER M5 ;
        RECT  9.504 0 9.528 0.084 ;
    END
  END cfg_data[36]
  PIN cfg_data[37]
    DIRECTION INPUT ;
    USE SIGNAL ;
    PORT
      LAYER M5 ;
        RECT  9.648 0 9.672 0.084 ;
    END
  END cfg_data[37]
  PIN cfg_data[38]
    DIRECTION INPUT ;
    USE SIGNAL ;
    PORT
      LAYER M5 ;
        RECT  9.84 0 9.864 0.084 ;
    END
  END cfg_data[38]
  PIN cfg_data[39]
    DIRECTION INPUT ;
    USE SIGNAL ;
    PORT
      LAYER M5 ;
        RECT  10.032 0 10.056 0.084 ;
    END
  END cfg_data[39]
  PIN cfg_data[3]
    DIRECTION INPUT ;
    USE SIGNAL ;
    PORT
      LAYER M5 ;
        RECT  3.84 0 3.864 0.084 ;
    END
  END cfg_data[3]
  PIN cfg_data[40]
    DIRECTION INPUT ;
    USE SIGNAL ;
    PORT
      LAYER M5 ;
        RECT  10.176 0 10.2 0.084 ;
    END
  END cfg_data[40]
  PIN cfg_data[41]
    DIRECTION INPUT ;
    USE SIGNAL ;
    PORT
      LAYER M5 ;
        RECT  10.368 0 10.392 0.084 ;
    END
  END cfg_data[41]
  PIN cfg_data[42]
    DIRECTION INPUT ;
    USE SIGNAL ;
    PORT
      LAYER M5 ;
        RECT  10.512 0 10.536 0.084 ;
    END
  END cfg_data[42]
  PIN cfg_data[43]
    DIRECTION INPUT ;
    USE SIGNAL ;
    PORT
      LAYER M5 ;
        RECT  10.704 0 10.728 0.084 ;
    END
  END cfg_data[43]
  PIN cfg_data[44]
    DIRECTION INPUT ;
    USE SIGNAL ;
    PORT
      LAYER M5 ;
        RECT  10.848 0 10.872 0.084 ;
    END
  END cfg_data[44]
  PIN cfg_data[45]
    DIRECTION INPUT ;
    USE SIGNAL ;
    PORT
      LAYER M5 ;
        RECT  11.04 0 11.064 0.084 ;
    END
  END cfg_data[45]
  PIN cfg_data[46]
    DIRECTION INPUT ;
    USE SIGNAL ;
    PORT
      LAYER M5 ;
        RECT  11.232 0 11.256 0.084 ;
    END
  END cfg_data[46]
  PIN cfg_data[47]
    DIRECTION INPUT ;
    USE SIGNAL ;
    PORT
      LAYER M5 ;
        RECT  11.376 0 11.4 0.084 ;
    END
  END cfg_data[47]
  PIN cfg_data[48]
    DIRECTION INPUT ;
    USE SIGNAL ;
    PORT
      LAYER M5 ;
        RECT  11.568 0 11.592 0.084 ;
    END
  END cfg_data[48]
  PIN cfg_data[49]
    DIRECTION INPUT ;
    USE SIGNAL ;
    PORT
      LAYER M5 ;
        RECT  11.712 0 11.736 0.084 ;
    END
  END cfg_data[49]
  PIN cfg_data[4]
    DIRECTION INPUT ;
    USE SIGNAL ;
    PORT
      LAYER M5 ;
        RECT  3.984 0 4.008 0.084 ;
    END
  END cfg_data[4]
  PIN cfg_data[50]
    DIRECTION INPUT ;
    USE SIGNAL ;
    PORT
      LAYER M5 ;
        RECT  11.904 0 11.928 0.084 ;
    END
  END cfg_data[50]
  PIN cfg_data[51]
    DIRECTION INPUT ;
    USE SIGNAL ;
    PORT
      LAYER M5 ;
        RECT  12.096 0 12.12 0.084 ;
    END
  END cfg_data[51]
  PIN cfg_data[52]
    DIRECTION INPUT ;
    USE SIGNAL ;
    PORT
      LAYER M5 ;
        RECT  12.24 0 12.264 0.084 ;
    END
  END cfg_data[52]
  PIN cfg_data[53]
    DIRECTION INPUT ;
    USE SIGNAL ;
    PORT
      LAYER M5 ;
        RECT  12.432 0 12.456 0.084 ;
    END
  END cfg_data[53]
  PIN cfg_data[54]
    DIRECTION INPUT ;
    USE SIGNAL ;
    PORT
      LAYER M5 ;
        RECT  12.576 0 12.6 0.084 ;
    END
  END cfg_data[54]
  PIN cfg_data[55]
    DIRECTION INPUT ;
    USE SIGNAL ;
    PORT
      LAYER M5 ;
        RECT  12.768 0 12.792 0.084 ;
    END
  END cfg_data[55]
  PIN cfg_data[56]
    DIRECTION INPUT ;
    USE SIGNAL ;
    PORT
      LAYER M5 ;
        RECT  12.912 0 12.936 0.084 ;
    END
  END cfg_data[56]
  PIN cfg_data[57]
    DIRECTION INPUT ;
    USE SIGNAL ;
    PORT
      LAYER M5 ;
        RECT  13.104 0 13.128 0.084 ;
    END
  END cfg_data[57]
  PIN cfg_data[58]
    DIRECTION INPUT ;
    USE SIGNAL ;
    PORT
      LAYER M5 ;
        RECT  13.296 0 13.32 0.084 ;
    END
  END cfg_data[58]
  PIN cfg_data[59]
    DIRECTION INPUT ;
    USE SIGNAL ;
    PORT
      LAYER M5 ;
        RECT  13.44 0 13.464 0.084 ;
    END
  END cfg_data[59]
  PIN cfg_data[5]
    DIRECTION INPUT ;
    USE SIGNAL ;
    PORT
      LAYER M5 ;
        RECT  4.176 0 4.2 0.084 ;
    END
  END cfg_data[5]
  PIN cfg_data[60]
    DIRECTION INPUT ;
    USE SIGNAL ;
    PORT
      LAYER M5 ;
        RECT  13.632 0 13.656 0.084 ;
    END
  END cfg_data[60]
  PIN cfg_data[61]
    DIRECTION INPUT ;
    USE SIGNAL ;
    PORT
      LAYER M5 ;
        RECT  13.776 0 13.8 0.084 ;
    END
  END cfg_data[61]
  PIN cfg_data[62]
    DIRECTION INPUT ;
    USE SIGNAL ;
    PORT
      LAYER M5 ;
        RECT  13.968 0 13.992 0.084 ;
    END
  END cfg_data[62]
  PIN cfg_data[63]
    DIRECTION INPUT ;
    USE SIGNAL ;
    PORT
      LAYER M5 ;
        RECT  14.112 0 14.136 0.084 ;
    END
  END cfg_data[63]
  PIN cfg_data[64]
    DIRECTION INPUT ;
    USE SIGNAL ;
    PORT
      LAYER M5 ;
        RECT  14.304 0 14.328 0.084 ;
    END
  END cfg_data[64]
  PIN cfg_data[65]
    DIRECTION INPUT ;
    USE SIGNAL ;
    PORT
      LAYER M5 ;
        RECT  14.496 0 14.52 0.084 ;
    END
  END cfg_data[65]
  PIN cfg_data[66]
    DIRECTION INPUT ;
    USE SIGNAL ;
    PORT
      LAYER M5 ;
        RECT  14.64 0 14.664 0.084 ;
    END
  END cfg_data[66]
  PIN cfg_data[67]
    DIRECTION INPUT ;
    USE SIGNAL ;
    PORT
      LAYER M5 ;
        RECT  14.832 0 14.856 0.084 ;
    END
  END cfg_data[67]
  PIN cfg_data[68]
    DIRECTION INPUT ;
    USE SIGNAL ;
    PORT
      LAYER M5 ;
        RECT  14.976 0 15 0.084 ;
    END
  END cfg_data[68]
  PIN cfg_data[69]
    DIRECTION INPUT ;
    USE SIGNAL ;
    PORT
      LAYER M5 ;
        RECT  15.168 0 15.192 0.084 ;
    END
  END cfg_data[69]
  PIN cfg_data[6]
    DIRECTION INPUT ;
    USE SIGNAL ;
    PORT
      LAYER M5 ;
        RECT  4.32 0 4.344 0.084 ;
    END
  END cfg_data[6]
  PIN cfg_data[70]
    DIRECTION INPUT ;
    USE SIGNAL ;
    PORT
      LAYER M5 ;
        RECT  15.36 0 15.384 0.084 ;
    END
  END cfg_data[70]
  PIN cfg_data[71]
    DIRECTION INPUT ;
    USE SIGNAL ;
    PORT
      LAYER M5 ;
        RECT  15.504 0 15.528 0.084 ;
    END
  END cfg_data[71]
  PIN cfg_data[72]
    DIRECTION INPUT ;
    USE SIGNAL ;
    PORT
      LAYER M5 ;
        RECT  15.696 0 15.72 0.084 ;
    END
  END cfg_data[72]
  PIN cfg_data[73]
    DIRECTION INPUT ;
    USE SIGNAL ;
    PORT
      LAYER M5 ;
        RECT  15.84 0 15.864 0.084 ;
    END
  END cfg_data[73]
  PIN cfg_data[74]
    DIRECTION INPUT ;
    USE SIGNAL ;
    PORT
      LAYER M5 ;
        RECT  16.032 0 16.056 0.084 ;
    END
  END cfg_data[74]
  PIN cfg_data[75]
    DIRECTION INPUT ;
    USE SIGNAL ;
    PORT
      LAYER M5 ;
        RECT  16.176 0 16.2 0.084 ;
    END
  END cfg_data[75]
  PIN cfg_data[76]
    DIRECTION INPUT ;
    USE SIGNAL ;
    PORT
      LAYER M5 ;
        RECT  16.368 0 16.392 0.084 ;
    END
  END cfg_data[76]
  PIN cfg_data[77]
    DIRECTION INPUT ;
    USE SIGNAL ;
    PORT
      LAYER M5 ;
        RECT  16.56 0 16.584 0.084 ;
    END
  END cfg_data[77]
  PIN cfg_data[78]
    DIRECTION INPUT ;
    USE SIGNAL ;
    PORT
      LAYER M5 ;
        RECT  16.704 0 16.728 0.084 ;
    END
  END cfg_data[78]
  PIN cfg_data[79]
    DIRECTION INPUT ;
    USE SIGNAL ;
    PORT
      LAYER M5 ;
        RECT  16.896 0 16.92 0.084 ;
    END
  END cfg_data[79]
  PIN cfg_data[7]
    DIRECTION INPUT ;
    USE SIGNAL ;
    PORT
      LAYER M5 ;
        RECT  4.512 0 4.536 0.084 ;
    END
  END cfg_data[7]
  PIN cfg_data[80]
    DIRECTION INPUT ;
    USE SIGNAL ;
    PORT
      LAYER M5 ;
        RECT  17.04 0 17.064 0.084 ;
    END
  END cfg_data[80]
  PIN cfg_data[81]
    DIRECTION INPUT ;
    USE SIGNAL ;
    PORT
      LAYER M5 ;
        RECT  17.232 0 17.256 0.084 ;
    END
  END cfg_data[81]
  PIN cfg_data[82]
    DIRECTION INPUT ;
    USE SIGNAL ;
    PORT
      LAYER M5 ;
        RECT  17.424 0 17.448 0.084 ;
    END
  END cfg_data[82]
  PIN cfg_data[83]
    DIRECTION INPUT ;
    USE SIGNAL ;
    PORT
      LAYER M5 ;
        RECT  17.568 0 17.592 0.084 ;
    END
  END cfg_data[83]
  PIN cfg_data[84]
    DIRECTION INPUT ;
    USE SIGNAL ;
    PORT
      LAYER M5 ;
        RECT  17.76 0 17.784 0.084 ;
    END
  END cfg_data[84]
  PIN cfg_data[85]
    DIRECTION INPUT ;
    USE SIGNAL ;
    PORT
      LAYER M5 ;
        RECT  17.904 0 17.928 0.084 ;
    END
  END cfg_data[85]
  PIN cfg_data[86]
    DIRECTION INPUT ;
    USE SIGNAL ;
    PORT
      LAYER M5 ;
        RECT  18.096 0 18.12 0.084 ;
    END
  END cfg_data[86]
  PIN cfg_data[87]
    DIRECTION INPUT ;
    USE SIGNAL ;
    PORT
      LAYER M5 ;
        RECT  18.24 0 18.264 0.084 ;
    END
  END cfg_data[87]
  PIN cfg_data[88]
    DIRECTION INPUT ;
    USE SIGNAL ;
    PORT
      LAYER M5 ;
        RECT  18.432 0 18.456 0.084 ;
    END
  END cfg_data[88]
  PIN cfg_data[89]
    DIRECTION INPUT ;
    USE SIGNAL ;
    PORT
      LAYER M5 ;
        RECT  18.624 0 18.648 0.084 ;
    END
  END cfg_data[89]
  PIN cfg_data[8]
    DIRECTION INPUT ;
    USE SIGNAL ;
    PORT
      LAYER M5 ;
        RECT  4.704 0 4.728 0.084 ;
    END
  END cfg_data[8]
  PIN cfg_data[90]
    DIRECTION INPUT ;
    USE SIGNAL ;
    PORT
      LAYER M5 ;
        RECT  18.768 0 18.792 0.084 ;
    END
  END cfg_data[90]
  PIN cfg_data[91]
    DIRECTION INPUT ;
    USE SIGNAL ;
    PORT
      LAYER M5 ;
        RECT  18.96 0 18.984 0.084 ;
    END
  END cfg_data[91]
  PIN cfg_data[92]
    DIRECTION INPUT ;
    USE SIGNAL ;
    PORT
      LAYER M5 ;
        RECT  19.104 0 19.128 0.084 ;
    END
  END cfg_data[92]
  PIN cfg_data[93]
    DIRECTION INPUT ;
    USE SIGNAL ;
    PORT
      LAYER M5 ;
        RECT  19.296 0 19.32 0.084 ;
    END
  END cfg_data[93]
  PIN cfg_data[94]
    DIRECTION INPUT ;
    USE SIGNAL ;
    PORT
      LAYER M5 ;
        RECT  19.44 0 19.464 0.084 ;
    END
  END cfg_data[94]
  PIN cfg_data[95]
    DIRECTION INPUT ;
    USE SIGNAL ;
    PORT
      LAYER M5 ;
        RECT  19.632 0 19.656 0.084 ;
    END
  END cfg_data[95]
  PIN cfg_data[96]
    DIRECTION INPUT ;
    USE SIGNAL ;
    PORT
      LAYER M5 ;
        RECT  19.824 0 19.848 0.084 ;
    END
  END cfg_data[96]
  PIN cfg_data[97]
    DIRECTION INPUT ;
    USE SIGNAL ;
    PORT
      LAYER M5 ;
        RECT  19.968 0 19.992 0.084 ;
    END
  END cfg_data[97]
  PIN cfg_data[98]
    DIRECTION INPUT ;
    USE SIGNAL ;
    PORT
      LAYER M5 ;
        RECT  20.16 0 20.184 0.084 ;
    END
  END cfg_data[98]
  PIN cfg_data[99]
    DIRECTION INPUT ;
    USE SIGNAL ;
    PORT
      LAYER M5 ;
        RECT  20.304 0 20.328 0.084 ;
    END
  END cfg_data[99]
  PIN cfg_data[9]
    DIRECTION INPUT ;
    USE SIGNAL ;
    PORT
      LAYER M5 ;
        RECT  4.848 0 4.872 0.084 ;
    END
  END cfg_data[9]
  PIN cfg_target[0]
    DIRECTION INPUT ;
    USE SIGNAL ;
    PORT
      LAYER M5 ;
        RECT  47.328 0 47.352 0.084 ;
    END
  END cfg_target[0]
  PIN cfg_target[1]
    DIRECTION INPUT ;
    USE SIGNAL ;
    PORT
      LAYER M5 ;
        RECT  47.472 0 47.496 0.084 ;
    END
  END cfg_target[1]
  PIN cfg_target[2]
    DIRECTION INPUT ;
    USE SIGNAL ;
    PORT
      LAYER M5 ;
        RECT  47.664 0 47.688 0.084 ;
    END
  END cfg_target[2]
  PIN cfg_target[3]
    DIRECTION INPUT ;
    USE SIGNAL ;
    PORT
      LAYER M5 ;
        RECT  47.808 0 47.832 0.084 ;
    END
  END cfg_target[3]
  PIN cfg_target[4]
    DIRECTION INPUT ;
    USE SIGNAL ;
    PORT
      LAYER M5 ;
        RECT  48 0 48.024 0.084 ;
    END
  END cfg_target[4]
  PIN cfg_target[5]
    DIRECTION INPUT ;
    USE SIGNAL ;
    PORT
      LAYER M5 ;
        RECT  48.144 0 48.168 0.084 ;
    END
  END cfg_target[5]
  PIN cfg_target[6]
    DIRECTION INPUT ;
    USE SIGNAL ;
    PORT
      LAYER M5 ;
        RECT  48.336 0 48.36 0.084 ;
    END
  END cfg_target[6]
  PIN cfg_target[7]
    DIRECTION INPUT ;
    USE SIGNAL ;
    PORT
      LAYER M5 ;
        RECT  48.528 0 48.552 0.084 ;
    END
  END cfg_target[7]
  PIN cfg_v
    DIRECTION INPUT ;
    USE SIGNAL ;
    PORT
      LAYER M5 ;
        RECT  48.672 0 48.696 0.084 ;
    END
  END cfg_v
  PIN clk
    DIRECTION INPUT ;
    USE SIGNAL ;
    PORT
      LAYER M5 ;
        RECT  48.864 0 48.888 0.084 ;
    END
  END clk
  PIN clk_hbm
    DIRECTION INPUT ;
    USE SIGNAL ;
    PORT
      LAYER M5 ;
        RECT  1.2 51.756 1.224 51.84 ;
    END
  END clk_hbm
  PIN fault
    DIRECTION OUTPUT ;
    USE SIGNAL ;
    PORT
      LAYER M5 ;
        RECT  49.008 0 49.032 0.084 ;
    END
  END fault
  PIN pc_rst_n
    DIRECTION OUTPUT ;
    USE SIGNAL ;
    PORT
      LAYER M5 ;
        RECT  1.536 51.756 1.56 51.84 ;
    END
  END pc_rst_n
  PIN ready
    DIRECTION OUTPUT ;
    USE SIGNAL ;
    PORT
      LAYER M5 ;
        RECT  49.2 0 49.224 0.084 ;
    END
  END ready
  PIN refresh_reload[0]
    DIRECTION OUTPUT ;
    USE SIGNAL ;
    PORT
      LAYER M5 ;
        RECT  1.92 51.756 1.944 51.84 ;
    END
  END refresh_reload[0]
  PIN refresh_reload[100]
    DIRECTION OUTPUT ;
    USE SIGNAL ;
    PORT
      LAYER M5 ;
        RECT  39.984 51.756 40.008 51.84 ;
    END
  END refresh_reload[100]
  PIN refresh_reload[101]
    DIRECTION OUTPUT ;
    USE SIGNAL ;
    PORT
      LAYER M5 ;
        RECT  40.368 51.756 40.392 51.84 ;
    END
  END refresh_reload[101]
  PIN refresh_reload[102]
    DIRECTION OUTPUT ;
    USE SIGNAL ;
    PORT
      LAYER M5 ;
        RECT  40.752 51.756 40.776 51.84 ;
    END
  END refresh_reload[102]
  PIN refresh_reload[103]
    DIRECTION OUTPUT ;
    USE SIGNAL ;
    PORT
      LAYER M5 ;
        RECT  41.136 51.756 41.16 51.84 ;
    END
  END refresh_reload[103]
  PIN refresh_reload[104]
    DIRECTION OUTPUT ;
    USE SIGNAL ;
    PORT
      LAYER M5 ;
        RECT  41.52 51.756 41.544 51.84 ;
    END
  END refresh_reload[104]
  PIN refresh_reload[105]
    DIRECTION OUTPUT ;
    USE SIGNAL ;
    PORT
      LAYER M5 ;
        RECT  41.904 51.756 41.928 51.84 ;
    END
  END refresh_reload[105]
  PIN refresh_reload[106]
    DIRECTION OUTPUT ;
    USE SIGNAL ;
    PORT
      LAYER M5 ;
        RECT  42.288 51.756 42.312 51.84 ;
    END
  END refresh_reload[106]
  PIN refresh_reload[107]
    DIRECTION OUTPUT ;
    USE SIGNAL ;
    PORT
      LAYER M5 ;
        RECT  42.672 51.756 42.696 51.84 ;
    END
  END refresh_reload[107]
  PIN refresh_reload[108]
    DIRECTION OUTPUT ;
    USE SIGNAL ;
    PORT
      LAYER M5 ;
        RECT  43.008 51.756 43.032 51.84 ;
    END
  END refresh_reload[108]
  PIN refresh_reload[109]
    DIRECTION OUTPUT ;
    USE SIGNAL ;
    PORT
      LAYER M5 ;
        RECT  43.392 51.756 43.416 51.84 ;
    END
  END refresh_reload[109]
  PIN refresh_reload[10]
    DIRECTION OUTPUT ;
    USE SIGNAL ;
    PORT
      LAYER M5 ;
        RECT  5.76 51.756 5.784 51.84 ;
    END
  END refresh_reload[10]
  PIN refresh_reload[110]
    DIRECTION OUTPUT ;
    USE SIGNAL ;
    PORT
      LAYER M5 ;
        RECT  43.776 51.756 43.8 51.84 ;
    END
  END refresh_reload[110]
  PIN refresh_reload[111]
    DIRECTION OUTPUT ;
    USE SIGNAL ;
    PORT
      LAYER M5 ;
        RECT  44.16 51.756 44.184 51.84 ;
    END
  END refresh_reload[111]
  PIN refresh_reload[112]
    DIRECTION OUTPUT ;
    USE SIGNAL ;
    PORT
      LAYER M5 ;
        RECT  44.544 51.756 44.568 51.84 ;
    END
  END refresh_reload[112]
  PIN refresh_reload[113]
    DIRECTION OUTPUT ;
    USE SIGNAL ;
    PORT
      LAYER M5 ;
        RECT  44.928 51.756 44.952 51.84 ;
    END
  END refresh_reload[113]
  PIN refresh_reload[114]
    DIRECTION OUTPUT ;
    USE SIGNAL ;
    PORT
      LAYER M5 ;
        RECT  45.312 51.756 45.336 51.84 ;
    END
  END refresh_reload[114]
  PIN refresh_reload[115]
    DIRECTION OUTPUT ;
    USE SIGNAL ;
    PORT
      LAYER M5 ;
        RECT  45.696 51.756 45.72 51.84 ;
    END
  END refresh_reload[115]
  PIN refresh_reload[116]
    DIRECTION OUTPUT ;
    USE SIGNAL ;
    PORT
      LAYER M5 ;
        RECT  46.08 51.756 46.104 51.84 ;
    END
  END refresh_reload[116]
  PIN refresh_reload[117]
    DIRECTION OUTPUT ;
    USE SIGNAL ;
    PORT
      LAYER M5 ;
        RECT  46.464 51.756 46.488 51.84 ;
    END
  END refresh_reload[117]
  PIN refresh_reload[118]
    DIRECTION OUTPUT ;
    USE SIGNAL ;
    PORT
      LAYER M5 ;
        RECT  46.848 51.756 46.872 51.84 ;
    END
  END refresh_reload[118]
  PIN refresh_reload[119]
    DIRECTION OUTPUT ;
    USE SIGNAL ;
    PORT
      LAYER M5 ;
        RECT  47.232 51.756 47.256 51.84 ;
    END
  END refresh_reload[119]
  PIN refresh_reload[11]
    DIRECTION OUTPUT ;
    USE SIGNAL ;
    PORT
      LAYER M5 ;
        RECT  6.144 51.756 6.168 51.84 ;
    END
  END refresh_reload[11]
  PIN refresh_reload[120]
    DIRECTION OUTPUT ;
    USE SIGNAL ;
    PORT
      LAYER M5 ;
        RECT  47.616 51.756 47.64 51.84 ;
    END
  END refresh_reload[120]
  PIN refresh_reload[121]
    DIRECTION OUTPUT ;
    USE SIGNAL ;
    PORT
      LAYER M5 ;
        RECT  47.952 51.756 47.976 51.84 ;
    END
  END refresh_reload[121]
  PIN refresh_reload[122]
    DIRECTION OUTPUT ;
    USE SIGNAL ;
    PORT
      LAYER M5 ;
        RECT  48.336 51.756 48.36 51.84 ;
    END
  END refresh_reload[122]
  PIN refresh_reload[123]
    DIRECTION OUTPUT ;
    USE SIGNAL ;
    PORT
      LAYER M5 ;
        RECT  48.72 51.756 48.744 51.84 ;
    END
  END refresh_reload[123]
  PIN refresh_reload[124]
    DIRECTION OUTPUT ;
    USE SIGNAL ;
    PORT
      LAYER M5 ;
        RECT  49.104 51.756 49.128 51.84 ;
    END
  END refresh_reload[124]
  PIN refresh_reload[125]
    DIRECTION OUTPUT ;
    USE SIGNAL ;
    PORT
      LAYER M5 ;
        RECT  49.488 51.756 49.512 51.84 ;
    END
  END refresh_reload[125]
  PIN refresh_reload[126]
    DIRECTION OUTPUT ;
    USE SIGNAL ;
    PORT
      LAYER M5 ;
        RECT  49.872 51.756 49.896 51.84 ;
    END
  END refresh_reload[126]
  PIN refresh_reload[127]
    DIRECTION OUTPUT ;
    USE SIGNAL ;
    PORT
      LAYER M5 ;
        RECT  50.256 51.756 50.28 51.84 ;
    END
  END refresh_reload[127]
  PIN refresh_reload[12]
    DIRECTION OUTPUT ;
    USE SIGNAL ;
    PORT
      LAYER M5 ;
        RECT  6.528 51.756 6.552 51.84 ;
    END
  END refresh_reload[12]
  PIN refresh_reload[13]
    DIRECTION OUTPUT ;
    USE SIGNAL ;
    PORT
      LAYER M5 ;
        RECT  6.864 51.756 6.888 51.84 ;
    END
  END refresh_reload[13]
  PIN refresh_reload[14]
    DIRECTION OUTPUT ;
    USE SIGNAL ;
    PORT
      LAYER M5 ;
        RECT  7.248 51.756 7.272 51.84 ;
    END
  END refresh_reload[14]
  PIN refresh_reload[15]
    DIRECTION OUTPUT ;
    USE SIGNAL ;
    PORT
      LAYER M5 ;
        RECT  7.632 51.756 7.656 51.84 ;
    END
  END refresh_reload[15]
  PIN refresh_reload[16]
    DIRECTION OUTPUT ;
    USE SIGNAL ;
    PORT
      LAYER M5 ;
        RECT  8.016 51.756 8.04 51.84 ;
    END
  END refresh_reload[16]
  PIN refresh_reload[17]
    DIRECTION OUTPUT ;
    USE SIGNAL ;
    PORT
      LAYER M5 ;
        RECT  8.4 51.756 8.424 51.84 ;
    END
  END refresh_reload[17]
  PIN refresh_reload[18]
    DIRECTION OUTPUT ;
    USE SIGNAL ;
    PORT
      LAYER M5 ;
        RECT  8.784 51.756 8.808 51.84 ;
    END
  END refresh_reload[18]
  PIN refresh_reload[19]
    DIRECTION OUTPUT ;
    USE SIGNAL ;
    PORT
      LAYER M5 ;
        RECT  9.168 51.756 9.192 51.84 ;
    END
  END refresh_reload[19]
  PIN refresh_reload[1]
    DIRECTION OUTPUT ;
    USE SIGNAL ;
    PORT
      LAYER M5 ;
        RECT  2.304 51.756 2.328 51.84 ;
    END
  END refresh_reload[1]
  PIN refresh_reload[20]
    DIRECTION OUTPUT ;
    USE SIGNAL ;
    PORT
      LAYER M5 ;
        RECT  9.552 51.756 9.576 51.84 ;
    END
  END refresh_reload[20]
  PIN refresh_reload[21]
    DIRECTION OUTPUT ;
    USE SIGNAL ;
    PORT
      LAYER M5 ;
        RECT  9.936 51.756 9.96 51.84 ;
    END
  END refresh_reload[21]
  PIN refresh_reload[22]
    DIRECTION OUTPUT ;
    USE SIGNAL ;
    PORT
      LAYER M5 ;
        RECT  10.32 51.756 10.344 51.84 ;
    END
  END refresh_reload[22]
  PIN refresh_reload[23]
    DIRECTION OUTPUT ;
    USE SIGNAL ;
    PORT
      LAYER M5 ;
        RECT  10.704 51.756 10.728 51.84 ;
    END
  END refresh_reload[23]
  PIN refresh_reload[24]
    DIRECTION OUTPUT ;
    USE SIGNAL ;
    PORT
      LAYER M5 ;
        RECT  11.088 51.756 11.112 51.84 ;
    END
  END refresh_reload[24]
  PIN refresh_reload[25]
    DIRECTION OUTPUT ;
    USE SIGNAL ;
    PORT
      LAYER M5 ;
        RECT  11.472 51.756 11.496 51.84 ;
    END
  END refresh_reload[25]
  PIN refresh_reload[26]
    DIRECTION OUTPUT ;
    USE SIGNAL ;
    PORT
      LAYER M5 ;
        RECT  11.808 51.756 11.832 51.84 ;
    END
  END refresh_reload[26]
  PIN refresh_reload[27]
    DIRECTION OUTPUT ;
    USE SIGNAL ;
    PORT
      LAYER M5 ;
        RECT  12.192 51.756 12.216 51.84 ;
    END
  END refresh_reload[27]
  PIN refresh_reload[28]
    DIRECTION OUTPUT ;
    USE SIGNAL ;
    PORT
      LAYER M5 ;
        RECT  12.576 51.756 12.6 51.84 ;
    END
  END refresh_reload[28]
  PIN refresh_reload[29]
    DIRECTION OUTPUT ;
    USE SIGNAL ;
    PORT
      LAYER M5 ;
        RECT  12.96 51.756 12.984 51.84 ;
    END
  END refresh_reload[29]
  PIN refresh_reload[2]
    DIRECTION OUTPUT ;
    USE SIGNAL ;
    PORT
      LAYER M5 ;
        RECT  2.688 51.756 2.712 51.84 ;
    END
  END refresh_reload[2]
  PIN refresh_reload[30]
    DIRECTION OUTPUT ;
    USE SIGNAL ;
    PORT
      LAYER M5 ;
        RECT  13.344 51.756 13.368 51.84 ;
    END
  END refresh_reload[30]
  PIN refresh_reload[31]
    DIRECTION OUTPUT ;
    USE SIGNAL ;
    PORT
      LAYER M5 ;
        RECT  13.728 51.756 13.752 51.84 ;
    END
  END refresh_reload[31]
  PIN refresh_reload[32]
    DIRECTION OUTPUT ;
    USE SIGNAL ;
    PORT
      LAYER M5 ;
        RECT  14.112 51.756 14.136 51.84 ;
    END
  END refresh_reload[32]
  PIN refresh_reload[33]
    DIRECTION OUTPUT ;
    USE SIGNAL ;
    PORT
      LAYER M5 ;
        RECT  14.496 51.756 14.52 51.84 ;
    END
  END refresh_reload[33]
  PIN refresh_reload[34]
    DIRECTION OUTPUT ;
    USE SIGNAL ;
    PORT
      LAYER M5 ;
        RECT  14.88 51.756 14.904 51.84 ;
    END
  END refresh_reload[34]
  PIN refresh_reload[35]
    DIRECTION OUTPUT ;
    USE SIGNAL ;
    PORT
      LAYER M5 ;
        RECT  15.264 51.756 15.288 51.84 ;
    END
  END refresh_reload[35]
  PIN refresh_reload[36]
    DIRECTION OUTPUT ;
    USE SIGNAL ;
    PORT
      LAYER M5 ;
        RECT  15.648 51.756 15.672 51.84 ;
    END
  END refresh_reload[36]
  PIN refresh_reload[37]
    DIRECTION OUTPUT ;
    USE SIGNAL ;
    PORT
      LAYER M5 ;
        RECT  16.032 51.756 16.056 51.84 ;
    END
  END refresh_reload[37]
  PIN refresh_reload[38]
    DIRECTION OUTPUT ;
    USE SIGNAL ;
    PORT
      LAYER M5 ;
        RECT  16.416 51.756 16.44 51.84 ;
    END
  END refresh_reload[38]
  PIN refresh_reload[39]
    DIRECTION OUTPUT ;
    USE SIGNAL ;
    PORT
      LAYER M5 ;
        RECT  16.8 51.756 16.824 51.84 ;
    END
  END refresh_reload[39]
  PIN refresh_reload[3]
    DIRECTION OUTPUT ;
    USE SIGNAL ;
    PORT
      LAYER M5 ;
        RECT  3.072 51.756 3.096 51.84 ;
    END
  END refresh_reload[3]
  PIN refresh_reload[40]
    DIRECTION OUTPUT ;
    USE SIGNAL ;
    PORT
      LAYER M5 ;
        RECT  17.136 51.756 17.16 51.84 ;
    END
  END refresh_reload[40]
  PIN refresh_reload[41]
    DIRECTION OUTPUT ;
    USE SIGNAL ;
    PORT
      LAYER M5 ;
        RECT  17.52 51.756 17.544 51.84 ;
    END
  END refresh_reload[41]
  PIN refresh_reload[42]
    DIRECTION OUTPUT ;
    USE SIGNAL ;
    PORT
      LAYER M5 ;
        RECT  17.904 51.756 17.928 51.84 ;
    END
  END refresh_reload[42]
  PIN refresh_reload[43]
    DIRECTION OUTPUT ;
    USE SIGNAL ;
    PORT
      LAYER M5 ;
        RECT  18.288 51.756 18.312 51.84 ;
    END
  END refresh_reload[43]
  PIN refresh_reload[44]
    DIRECTION OUTPUT ;
    USE SIGNAL ;
    PORT
      LAYER M5 ;
        RECT  18.672 51.756 18.696 51.84 ;
    END
  END refresh_reload[44]
  PIN refresh_reload[45]
    DIRECTION OUTPUT ;
    USE SIGNAL ;
    PORT
      LAYER M5 ;
        RECT  19.056 51.756 19.08 51.84 ;
    END
  END refresh_reload[45]
  PIN refresh_reload[46]
    DIRECTION OUTPUT ;
    USE SIGNAL ;
    PORT
      LAYER M5 ;
        RECT  19.44 51.756 19.464 51.84 ;
    END
  END refresh_reload[46]
  PIN refresh_reload[47]
    DIRECTION OUTPUT ;
    USE SIGNAL ;
    PORT
      LAYER M5 ;
        RECT  19.824 51.756 19.848 51.84 ;
    END
  END refresh_reload[47]
  PIN refresh_reload[48]
    DIRECTION OUTPUT ;
    USE SIGNAL ;
    PORT
      LAYER M5 ;
        RECT  20.208 51.756 20.232 51.84 ;
    END
  END refresh_reload[48]
  PIN refresh_reload[49]
    DIRECTION OUTPUT ;
    USE SIGNAL ;
    PORT
      LAYER M5 ;
        RECT  20.592 51.756 20.616 51.84 ;
    END
  END refresh_reload[49]
  PIN refresh_reload[4]
    DIRECTION OUTPUT ;
    USE SIGNAL ;
    PORT
      LAYER M5 ;
        RECT  3.456 51.756 3.48 51.84 ;
    END
  END refresh_reload[4]
  PIN refresh_reload[50]
    DIRECTION OUTPUT ;
    USE SIGNAL ;
    PORT
      LAYER M5 ;
        RECT  20.976 51.756 21 51.84 ;
    END
  END refresh_reload[50]
  PIN refresh_reload[51]
    DIRECTION OUTPUT ;
    USE SIGNAL ;
    PORT
      LAYER M5 ;
        RECT  21.36 51.756 21.384 51.84 ;
    END
  END refresh_reload[51]
  PIN refresh_reload[52]
    DIRECTION OUTPUT ;
    USE SIGNAL ;
    PORT
      LAYER M5 ;
        RECT  21.744 51.756 21.768 51.84 ;
    END
  END refresh_reload[52]
  PIN refresh_reload[53]
    DIRECTION OUTPUT ;
    USE SIGNAL ;
    PORT
      LAYER M5 ;
        RECT  22.08 51.756 22.104 51.84 ;
    END
  END refresh_reload[53]
  PIN refresh_reload[54]
    DIRECTION OUTPUT ;
    USE SIGNAL ;
    PORT
      LAYER M5 ;
        RECT  22.464 51.756 22.488 51.84 ;
    END
  END refresh_reload[54]
  PIN refresh_reload[55]
    DIRECTION OUTPUT ;
    USE SIGNAL ;
    PORT
      LAYER M5 ;
        RECT  22.848 51.756 22.872 51.84 ;
    END
  END refresh_reload[55]
  PIN refresh_reload[56]
    DIRECTION OUTPUT ;
    USE SIGNAL ;
    PORT
      LAYER M5 ;
        RECT  23.232 51.756 23.256 51.84 ;
    END
  END refresh_reload[56]
  PIN refresh_reload[57]
    DIRECTION OUTPUT ;
    USE SIGNAL ;
    PORT
      LAYER M5 ;
        RECT  23.616 51.756 23.64 51.84 ;
    END
  END refresh_reload[57]
  PIN refresh_reload[58]
    DIRECTION OUTPUT ;
    USE SIGNAL ;
    PORT
      LAYER M5 ;
        RECT  24 51.756 24.024 51.84 ;
    END
  END refresh_reload[58]
  PIN refresh_reload[59]
    DIRECTION OUTPUT ;
    USE SIGNAL ;
    PORT
      LAYER M5 ;
        RECT  24.384 51.756 24.408 51.84 ;
    END
  END refresh_reload[59]
  PIN refresh_reload[5]
    DIRECTION OUTPUT ;
    USE SIGNAL ;
    PORT
      LAYER M5 ;
        RECT  3.84 51.756 3.864 51.84 ;
    END
  END refresh_reload[5]
  PIN refresh_reload[60]
    DIRECTION OUTPUT ;
    USE SIGNAL ;
    PORT
      LAYER M5 ;
        RECT  24.768 51.756 24.792 51.84 ;
    END
  END refresh_reload[60]
  PIN refresh_reload[61]
    DIRECTION OUTPUT ;
    USE SIGNAL ;
    PORT
      LAYER M5 ;
        RECT  25.152 51.756 25.176 51.84 ;
    END
  END refresh_reload[61]
  PIN refresh_reload[62]
    DIRECTION OUTPUT ;
    USE SIGNAL ;
    PORT
      LAYER M5 ;
        RECT  25.536 51.756 25.56 51.84 ;
    END
  END refresh_reload[62]
  PIN refresh_reload[63]
    DIRECTION OUTPUT ;
    USE SIGNAL ;
    PORT
      LAYER M5 ;
        RECT  25.92 51.756 25.944 51.84 ;
    END
  END refresh_reload[63]
  PIN refresh_reload[64]
    DIRECTION OUTPUT ;
    USE SIGNAL ;
    PORT
      LAYER M5 ;
        RECT  26.304 51.756 26.328 51.84 ;
    END
  END refresh_reload[64]
  PIN refresh_reload[65]
    DIRECTION OUTPUT ;
    USE SIGNAL ;
    PORT
      LAYER M5 ;
        RECT  26.688 51.756 26.712 51.84 ;
    END
  END refresh_reload[65]
  PIN refresh_reload[66]
    DIRECTION OUTPUT ;
    USE SIGNAL ;
    PORT
      LAYER M5 ;
        RECT  27.072 51.756 27.096 51.84 ;
    END
  END refresh_reload[66]
  PIN refresh_reload[67]
    DIRECTION OUTPUT ;
    USE SIGNAL ;
    PORT
      LAYER M5 ;
        RECT  27.408 51.756 27.432 51.84 ;
    END
  END refresh_reload[67]
  PIN refresh_reload[68]
    DIRECTION OUTPUT ;
    USE SIGNAL ;
    PORT
      LAYER M5 ;
        RECT  27.792 51.756 27.816 51.84 ;
    END
  END refresh_reload[68]
  PIN refresh_reload[69]
    DIRECTION OUTPUT ;
    USE SIGNAL ;
    PORT
      LAYER M5 ;
        RECT  28.176 51.756 28.2 51.84 ;
    END
  END refresh_reload[69]
  PIN refresh_reload[6]
    DIRECTION OUTPUT ;
    USE SIGNAL ;
    PORT
      LAYER M5 ;
        RECT  4.224 51.756 4.248 51.84 ;
    END
  END refresh_reload[6]
  PIN refresh_reload[70]
    DIRECTION OUTPUT ;
    USE SIGNAL ;
    PORT
      LAYER M5 ;
        RECT  28.56 51.756 28.584 51.84 ;
    END
  END refresh_reload[70]
  PIN refresh_reload[71]
    DIRECTION OUTPUT ;
    USE SIGNAL ;
    PORT
      LAYER M5 ;
        RECT  28.944 51.756 28.968 51.84 ;
    END
  END refresh_reload[71]
  PIN refresh_reload[72]
    DIRECTION OUTPUT ;
    USE SIGNAL ;
    PORT
      LAYER M5 ;
        RECT  29.328 51.756 29.352 51.84 ;
    END
  END refresh_reload[72]
  PIN refresh_reload[73]
    DIRECTION OUTPUT ;
    USE SIGNAL ;
    PORT
      LAYER M5 ;
        RECT  29.712 51.756 29.736 51.84 ;
    END
  END refresh_reload[73]
  PIN refresh_reload[74]
    DIRECTION OUTPUT ;
    USE SIGNAL ;
    PORT
      LAYER M5 ;
        RECT  30.096 51.756 30.12 51.84 ;
    END
  END refresh_reload[74]
  PIN refresh_reload[75]
    DIRECTION OUTPUT ;
    USE SIGNAL ;
    PORT
      LAYER M5 ;
        RECT  30.48 51.756 30.504 51.84 ;
    END
  END refresh_reload[75]
  PIN refresh_reload[76]
    DIRECTION OUTPUT ;
    USE SIGNAL ;
    PORT
      LAYER M5 ;
        RECT  30.864 51.756 30.888 51.84 ;
    END
  END refresh_reload[76]
  PIN refresh_reload[77]
    DIRECTION OUTPUT ;
    USE SIGNAL ;
    PORT
      LAYER M5 ;
        RECT  31.248 51.756 31.272 51.84 ;
    END
  END refresh_reload[77]
  PIN refresh_reload[78]
    DIRECTION OUTPUT ;
    USE SIGNAL ;
    PORT
      LAYER M5 ;
        RECT  31.632 51.756 31.656 51.84 ;
    END
  END refresh_reload[78]
  PIN refresh_reload[79]
    DIRECTION OUTPUT ;
    USE SIGNAL ;
    PORT
      LAYER M5 ;
        RECT  32.016 51.756 32.04 51.84 ;
    END
  END refresh_reload[79]
  PIN refresh_reload[7]
    DIRECTION OUTPUT ;
    USE SIGNAL ;
    PORT
      LAYER M5 ;
        RECT  4.608 51.756 4.632 51.84 ;
    END
  END refresh_reload[7]
  PIN refresh_reload[80]
    DIRECTION OUTPUT ;
    USE SIGNAL ;
    PORT
      LAYER M5 ;
        RECT  32.4 51.756 32.424 51.84 ;
    END
  END refresh_reload[80]
  PIN refresh_reload[81]
    DIRECTION OUTPUT ;
    USE SIGNAL ;
    PORT
      LAYER M5 ;
        RECT  32.736 51.756 32.76 51.84 ;
    END
  END refresh_reload[81]
  PIN refresh_reload[82]
    DIRECTION OUTPUT ;
    USE SIGNAL ;
    PORT
      LAYER M5 ;
        RECT  33.12 51.756 33.144 51.84 ;
    END
  END refresh_reload[82]
  PIN refresh_reload[83]
    DIRECTION OUTPUT ;
    USE SIGNAL ;
    PORT
      LAYER M5 ;
        RECT  33.504 51.756 33.528 51.84 ;
    END
  END refresh_reload[83]
  PIN refresh_reload[84]
    DIRECTION OUTPUT ;
    USE SIGNAL ;
    PORT
      LAYER M5 ;
        RECT  33.888 51.756 33.912 51.84 ;
    END
  END refresh_reload[84]
  PIN refresh_reload[85]
    DIRECTION OUTPUT ;
    USE SIGNAL ;
    PORT
      LAYER M5 ;
        RECT  34.272 51.756 34.296 51.84 ;
    END
  END refresh_reload[85]
  PIN refresh_reload[86]
    DIRECTION OUTPUT ;
    USE SIGNAL ;
    PORT
      LAYER M5 ;
        RECT  34.656 51.756 34.68 51.84 ;
    END
  END refresh_reload[86]
  PIN refresh_reload[87]
    DIRECTION OUTPUT ;
    USE SIGNAL ;
    PORT
      LAYER M5 ;
        RECT  35.04 51.756 35.064 51.84 ;
    END
  END refresh_reload[87]
  PIN refresh_reload[88]
    DIRECTION OUTPUT ;
    USE SIGNAL ;
    PORT
      LAYER M5 ;
        RECT  35.424 51.756 35.448 51.84 ;
    END
  END refresh_reload[88]
  PIN refresh_reload[89]
    DIRECTION OUTPUT ;
    USE SIGNAL ;
    PORT
      LAYER M5 ;
        RECT  35.808 51.756 35.832 51.84 ;
    END
  END refresh_reload[89]
  PIN refresh_reload[8]
    DIRECTION OUTPUT ;
    USE SIGNAL ;
    PORT
      LAYER M5 ;
        RECT  4.992 51.756 5.016 51.84 ;
    END
  END refresh_reload[8]
  PIN refresh_reload[90]
    DIRECTION OUTPUT ;
    USE SIGNAL ;
    PORT
      LAYER M5 ;
        RECT  36.192 51.756 36.216 51.84 ;
    END
  END refresh_reload[90]
  PIN refresh_reload[91]
    DIRECTION OUTPUT ;
    USE SIGNAL ;
    PORT
      LAYER M5 ;
        RECT  36.576 51.756 36.6 51.84 ;
    END
  END refresh_reload[91]
  PIN refresh_reload[92]
    DIRECTION OUTPUT ;
    USE SIGNAL ;
    PORT
      LAYER M5 ;
        RECT  36.96 51.756 36.984 51.84 ;
    END
  END refresh_reload[92]
  PIN refresh_reload[93]
    DIRECTION OUTPUT ;
    USE SIGNAL ;
    PORT
      LAYER M5 ;
        RECT  37.344 51.756 37.368 51.84 ;
    END
  END refresh_reload[93]
  PIN refresh_reload[94]
    DIRECTION OUTPUT ;
    USE SIGNAL ;
    PORT
      LAYER M5 ;
        RECT  37.68 51.756 37.704 51.84 ;
    END
  END refresh_reload[94]
  PIN refresh_reload[95]
    DIRECTION OUTPUT ;
    USE SIGNAL ;
    PORT
      LAYER M5 ;
        RECT  38.064 51.756 38.088 51.84 ;
    END
  END refresh_reload[95]
  PIN refresh_reload[96]
    DIRECTION OUTPUT ;
    USE SIGNAL ;
    PORT
      LAYER M5 ;
        RECT  38.448 51.756 38.472 51.84 ;
    END
  END refresh_reload[96]
  PIN refresh_reload[97]
    DIRECTION OUTPUT ;
    USE SIGNAL ;
    PORT
      LAYER M5 ;
        RECT  38.832 51.756 38.856 51.84 ;
    END
  END refresh_reload[97]
  PIN refresh_reload[98]
    DIRECTION OUTPUT ;
    USE SIGNAL ;
    PORT
      LAYER M5 ;
        RECT  39.216 51.756 39.24 51.84 ;
    END
  END refresh_reload[98]
  PIN refresh_reload[99]
    DIRECTION OUTPUT ;
    USE SIGNAL ;
    PORT
      LAYER M5 ;
        RECT  39.6 51.756 39.624 51.84 ;
    END
  END refresh_reload[99]
  PIN refresh_reload[9]
    DIRECTION OUTPUT ;
    USE SIGNAL ;
    PORT
      LAYER M5 ;
        RECT  5.376 51.756 5.4 51.84 ;
    END
  END refresh_reload[9]
  PIN rst_hbm_n
    DIRECTION INPUT ;
    USE SIGNAL ;
    PORT
      LAYER M5 ;
        RECT  50.64 51.756 50.664 51.84 ;
    END
  END rst_hbm_n
  PIN rst_n
    DIRECTION INPUT ;
    USE SIGNAL ;
    PORT
      LAYER M5 ;
        RECT  49.344 0 49.368 0.084 ;
    END
  END rst_n
  PIN tgt[0]
    DIRECTION INPUT ;
    USE SIGNAL ;
    PORT
      LAYER M5 ;
        RECT  49.536 0 49.56 0.084 ;
    END
  END tgt[0]
  PIN tgt[1]
    DIRECTION INPUT ;
    USE SIGNAL ;
    PORT
      LAYER M5 ;
        RECT  49.728 0 49.752 0.084 ;
    END
  END tgt[1]
  PIN tgt[2]
    DIRECTION INPUT ;
    USE SIGNAL ;
    PORT
      LAYER M5 ;
        RECT  49.872 0 49.896 0.084 ;
    END
  END tgt[2]
  PIN tgt[3]
    DIRECTION INPUT ;
    USE SIGNAL ;
    PORT
      LAYER M5 ;
        RECT  50.064 0 50.088 0.084 ;
    END
  END tgt[3]
  PIN tgt[4]
    DIRECTION INPUT ;
    USE SIGNAL ;
    PORT
      LAYER M5 ;
        RECT  50.208 0 50.232 0.084 ;
    END
  END tgt[4]
  PIN tgt[5]
    DIRECTION INPUT ;
    USE SIGNAL ;
    PORT
      LAYER M5 ;
        RECT  50.4 0 50.424 0.084 ;
    END
  END tgt[5]
  PIN tgt[6]
    DIRECTION INPUT ;
    USE SIGNAL ;
    PORT
      LAYER M5 ;
        RECT  50.592 0 50.616 0.084 ;
    END
  END tgt[6]
  PIN tgt[7]
    DIRECTION INPUT ;
    USE SIGNAL ;
    PORT
      LAYER M5 ;
        RECT  50.736 0 50.76 0.084 ;
    END
  END tgt[7]
  PIN VDD
    DIRECTION INOUT ;
    USE POWER ;
    PORT
      LAYER M5 ;
        RECT  45.792 2.151 45.912 49.689 ;
        RECT  40.392 2.151 40.512 49.689 ;
        RECT  34.992 2.151 35.112 49.689 ;
        RECT  29.592 2.151 29.712 49.689 ;
        RECT  24.192 2.151 24.312 49.689 ;
        RECT  18.792 2.151 18.912 49.689 ;
        RECT  13.392 2.151 13.512 49.689 ;
        RECT  7.992 2.151 8.112 49.689 ;
        RECT  2.592 2.151 2.712 49.689 ;
    END
  END VDD
  PIN VSS
    DIRECTION INOUT ;
    USE GROUND ;
    PORT
      LAYER M5 ;
        RECT  45.6 2.137 45.72 49.703 ;
        RECT  40.2 2.137 40.32 49.703 ;
        RECT  34.8 2.137 34.92 49.703 ;
        RECT  29.4 2.137 29.52 49.703 ;
        RECT  24 2.137 24.12 49.703 ;
        RECT  18.6 2.137 18.72 49.703 ;
        RECT  13.2 2.137 13.32 49.703 ;
        RECT  7.8 2.137 7.92 49.703 ;
        RECT  2.4 2.137 2.52 49.703 ;
    END
  END VSS
  # OT_OBS_CLOSED layer=M5 d_um=1.536 added=55
  OBS
    LAYER RVTN ;
     RECT  2.16 2.16 49.68 2.295 ;
     RECT  2.16 2.565 49.68 2.835 ;
     RECT  2.16 3.105 49.68 3.375 ;
     RECT  2.16 3.645 49.68 3.915 ;
     RECT  2.16 4.185 49.68 4.455 ;
     RECT  2.16 4.725 49.68 4.995 ;
     RECT  2.16 5.265 49.68 5.535 ;
     RECT  2.16 5.805 49.68 6.075 ;
     RECT  2.16 6.345 49.68 6.615 ;
     RECT  2.16 6.885 49.68 7.155 ;
     RECT  2.16 7.425 49.68 7.695 ;
     RECT  2.16 7.965 49.68 8.235 ;
     RECT  2.16 8.505 49.68 8.775 ;
     RECT  2.16 9.045 49.68 9.315 ;
     RECT  2.16 9.585 49.68 9.855 ;
     RECT  2.16 10.125 49.68 10.395 ;
     RECT  2.16 10.665 49.68 10.935 ;
     RECT  2.16 11.205 49.68 11.475 ;
     RECT  2.16 11.745 49.68 12.015 ;
     RECT  2.16 12.285 49.68 12.555 ;
     RECT  2.16 12.825 49.68 13.095 ;
     RECT  2.16 13.365 49.68 13.635 ;
     RECT  2.16 13.905 49.68 14.175 ;
     RECT  2.16 14.445 49.68 14.715 ;
     RECT  2.16 14.985 49.68 15.255 ;
     RECT  2.16 15.525 49.68 15.795 ;
     RECT  2.16 16.065 49.68 16.335 ;
     RECT  2.16 16.605 49.68 16.875 ;
     RECT  2.16 17.145 49.68 17.415 ;
     RECT  2.16 17.685 49.68 17.955 ;
     RECT  2.16 18.225 49.68 18.495 ;
     RECT  2.16 18.765 49.68 19.035 ;
     RECT  2.16 19.305 49.68 19.575 ;
     RECT  2.16 19.845 49.68 20.115 ;
     RECT  2.16 20.385 49.68 20.655 ;
     RECT  2.16 20.925 49.68 21.195 ;
     RECT  2.16 21.465 49.68 21.735 ;
     RECT  2.16 22.005 49.68 22.275 ;
     RECT  2.16 22.545 49.68 22.815 ;
     RECT  2.16 23.085 49.68 23.355 ;
     RECT  2.16 23.625 49.68 23.895 ;
     RECT  2.16 24.165 49.68 24.435 ;
     RECT  2.16 24.705 49.68 24.975 ;
     RECT  2.16 25.245 49.68 25.515 ;
     RECT  2.16 25.785 49.68 26.055 ;
     RECT  2.16 26.325 49.68 26.595 ;
     RECT  2.16 26.865 49.68 27.135 ;
     RECT  2.16 27.405 49.68 27.675 ;
     RECT  2.16 27.945 49.68 28.215 ;
     RECT  2.16 28.485 49.68 28.755 ;
     RECT  2.16 29.025 49.68 29.295 ;
     RECT  2.16 29.565 49.68 29.835 ;
     RECT  2.16 30.105 49.68 30.375 ;
     RECT  2.16 30.645 49.68 30.915 ;
     RECT  2.16 31.185 49.68 31.455 ;
     RECT  2.16 31.725 49.68 31.995 ;
     RECT  2.16 32.265 49.68 32.535 ;
     RECT  2.16 32.805 49.68 33.075 ;
     RECT  2.16 33.345 49.68 33.615 ;
     RECT  2.16 33.885 49.68 34.155 ;
     RECT  2.16 34.425 49.68 34.695 ;
     RECT  2.16 34.965 49.68 35.235 ;
     RECT  2.16 35.505 49.68 35.775 ;
     RECT  2.16 36.045 49.68 36.315 ;
     RECT  2.16 36.585 49.68 36.855 ;
     RECT  2.16 37.125 49.68 37.395 ;
     RECT  2.16 37.665 49.68 37.935 ;
     RECT  2.16 38.205 49.68 38.475 ;
     RECT  2.16 38.745 49.68 39.015 ;
     RECT  2.16 39.285 49.68 39.555 ;
     RECT  2.16 39.825 49.68 40.095 ;
     RECT  2.16 40.365 49.68 40.635 ;
     RECT  2.16 40.905 49.68 41.175 ;
     RECT  2.16 41.445 49.68 41.715 ;
     RECT  2.16 41.985 49.68 42.255 ;
     RECT  2.16 42.525 49.68 42.795 ;
     RECT  2.16 43.065 49.68 43.335 ;
     RECT  2.16 43.605 49.68 43.875 ;
     RECT  2.16 44.145 49.68 44.415 ;
     RECT  2.16 44.685 49.68 44.955 ;
     RECT  2.16 45.225 49.68 45.495 ;
     RECT  2.16 45.765 49.68 46.035 ;
     RECT  2.16 46.305 49.68 46.575 ;
     RECT  2.16 46.845 49.68 47.115 ;
     RECT  2.16 47.385 49.68 47.655 ;
     RECT  2.16 47.925 49.68 48.195 ;
     RECT  2.16 48.465 49.68 48.735 ;
     RECT  2.16 49.005 49.68 49.275 ;
     RECT  2.16 49.545 49.68 49.68 ;
    LAYER RVTP ;
     RECT  2.16 2.295 49.68 2.565 ;
     RECT  2.16 2.835 49.68 3.105 ;
     RECT  2.16 3.375 49.68 3.645 ;
     RECT  2.16 3.915 49.68 4.185 ;
     RECT  2.16 4.455 49.68 4.725 ;
     RECT  2.16 4.995 49.68 5.265 ;
     RECT  2.16 5.535 49.68 5.805 ;
     RECT  2.16 6.075 49.68 6.345 ;
     RECT  2.16 6.615 49.68 6.885 ;
     RECT  2.16 7.155 49.68 7.425 ;
     RECT  2.16 7.695 49.68 7.965 ;
     RECT  2.16 8.235 49.68 8.505 ;
     RECT  2.16 8.775 49.68 9.045 ;
     RECT  2.16 9.315 49.68 9.585 ;
     RECT  2.16 9.855 49.68 10.125 ;
     RECT  2.16 10.395 49.68 10.665 ;
     RECT  2.16 10.935 49.68 11.205 ;
     RECT  2.16 11.475 49.68 11.745 ;
     RECT  2.16 12.015 49.68 12.285 ;
     RECT  2.16 12.555 49.68 12.825 ;
     RECT  2.16 13.095 49.68 13.365 ;
     RECT  2.16 13.635 49.68 13.905 ;
     RECT  2.16 14.175 49.68 14.445 ;
     RECT  2.16 14.715 49.68 14.985 ;
     RECT  2.16 15.255 49.68 15.525 ;
     RECT  2.16 15.795 49.68 16.065 ;
     RECT  2.16 16.335 49.68 16.605 ;
     RECT  2.16 16.875 49.68 17.145 ;
     RECT  2.16 17.415 49.68 17.685 ;
     RECT  2.16 17.955 49.68 18.225 ;
     RECT  2.16 18.495 49.68 18.765 ;
     RECT  2.16 19.035 49.68 19.305 ;
     RECT  2.16 19.575 49.68 19.845 ;
     RECT  2.16 20.115 49.68 20.385 ;
     RECT  2.16 20.655 49.68 20.925 ;
     RECT  2.16 21.195 49.68 21.465 ;
     RECT  2.16 21.735 49.68 22.005 ;
     RECT  2.16 22.275 49.68 22.545 ;
     RECT  2.16 22.815 49.68 23.085 ;
     RECT  2.16 23.355 49.68 23.625 ;
     RECT  2.16 23.895 49.68 24.165 ;
     RECT  2.16 24.435 49.68 24.705 ;
     RECT  2.16 24.975 49.68 25.245 ;
     RECT  2.16 25.515 49.68 25.785 ;
     RECT  2.16 26.055 49.68 26.325 ;
     RECT  2.16 26.595 49.68 26.865 ;
     RECT  2.16 27.135 49.68 27.405 ;
     RECT  2.16 27.675 49.68 27.945 ;
     RECT  2.16 28.215 49.68 28.485 ;
     RECT  2.16 28.755 49.68 29.025 ;
     RECT  2.16 29.295 49.68 29.565 ;
     RECT  2.16 29.835 49.68 30.105 ;
     RECT  2.16 30.375 49.68 30.645 ;
     RECT  2.16 30.915 49.68 31.185 ;
     RECT  2.16 31.455 49.68 31.725 ;
     RECT  2.16 31.995 49.68 32.265 ;
     RECT  2.16 32.535 49.68 32.805 ;
     RECT  2.16 33.075 49.68 33.345 ;
     RECT  2.16 33.615 49.68 33.885 ;
     RECT  2.16 34.155 49.68 34.425 ;
     RECT  2.16 34.695 49.68 34.965 ;
     RECT  2.16 35.235 49.68 35.505 ;
     RECT  2.16 35.775 49.68 36.045 ;
     RECT  2.16 36.315 49.68 36.585 ;
     RECT  2.16 36.855 49.68 37.125 ;
     RECT  2.16 37.395 49.68 37.665 ;
     RECT  2.16 37.935 49.68 38.205 ;
     RECT  2.16 38.475 49.68 38.745 ;
     RECT  2.16 39.015 49.68 39.285 ;
     RECT  2.16 39.555 49.68 39.825 ;
     RECT  2.16 40.095 49.68 40.365 ;
     RECT  2.16 40.635 49.68 40.905 ;
     RECT  2.16 41.175 49.68 41.445 ;
     RECT  2.16 41.715 49.68 41.985 ;
     RECT  2.16 42.255 49.68 42.525 ;
     RECT  2.16 42.795 49.68 43.065 ;
     RECT  2.16 43.335 49.68 43.605 ;
     RECT  2.16 43.875 49.68 44.145 ;
     RECT  2.16 44.415 49.68 44.685 ;
     RECT  2.16 44.955 49.68 45.225 ;
     RECT  2.16 45.495 49.68 45.765 ;
     RECT  2.16 46.035 49.68 46.305 ;
     RECT  2.16 46.575 49.68 46.845 ;
     RECT  2.16 47.115 49.68 47.385 ;
     RECT  2.16 47.655 49.68 47.925 ;
     RECT  2.16 48.195 49.68 48.465 ;
     RECT  2.16 48.735 49.68 49.005 ;
     RECT  2.16 49.275 49.68 49.545 ;
    LAYER M1 ;
     RECT  2.16 2.151 49.68 49.689 ;
    LAYER M2 ;
     RECT  1.075 2.106 1.795 2.124 ;
     RECT  1.795 2.106 1.939 2.52 ;
     RECT  1.939 2.106 2.16 2.628 ;
     RECT  2.119 5.472 2.16 5.49 ;
     RECT  1.543 49.176 2.16 49.194 ;
     RECT  2.16 2.106 3.731 49.689 ;
     RECT  3.731 2.151 46.579 49.689 ;
     RECT  46.579 2.106 47.119 49.689 ;
     RECT  47.119 2.034 48.407 49.689 ;
     RECT  48.407 2.106 48.551 49.689 ;
     RECT  48.551 2.151 49.68 49.689 ;
     RECT  49.68 3.042 49.739 3.06 ;
     RECT  49.68 49.356 50.207 49.374 ;
    LAYER M3 ;
     RECT  49.248 0.427 49.986 0.475 ;
     RECT  49.176 0.475 49.986 0.523 ;
     RECT  48.852 0.523 49.986 0.557 ;
     RECT  46.944 0.091 46.962 0.571 ;
     RECT  48.852 0.557 49.626 0.571 ;
     RECT  46.944 0.571 49.626 1.675 ;
     RECT  7.956 0.091 7.974 1.723 ;
     RECT  20.016 0.043 20.034 1.723 ;
     RECT  46.944 1.675 49.734 2.101 ;
     RECT  1.08 1.723 25.218 2.129 ;
     RECT  1.8 2.129 25.218 2.191 ;
     RECT  29.415 2.143 29.505 2.413 ;
     RECT  34.815 2.143 34.905 2.413 ;
     RECT  40.215 2.143 40.305 2.413 ;
     RECT  45.615 2.143 45.705 2.413 ;
     RECT  46.584 2.101 49.734 2.413 ;
     RECT  1.8 2.191 25.398 2.525 ;
     RECT  1.944 2.525 25.398 2.633 ;
     RECT  2.376 2.633 25.398 2.767 ;
     RECT  45.615 2.413 49.734 3.065 ;
     RECT  45.615 3.065 49.626 3.569 ;
     RECT  42.768 3.547 42.786 3.677 ;
     RECT  2.376 2.767 25.902 3.721 ;
     RECT  46.692 3.569 49.626 3.749 ;
     RECT  47.16 3.749 49.626 3.875 ;
     RECT  2.376 3.721 26.226 3.979 ;
     RECT  2.124 3.979 26.226 4.685 ;
     RECT  2.124 4.685 10.422 4.919 ;
     RECT  11.268 4.685 26.226 4.919 ;
     RECT  11.448 4.919 26.226 5.189 ;
     RECT  47.196 3.875 49.626 5.341 ;
     RECT  2.124 4.919 7.002 5.495 ;
     RECT  47.016 5.341 49.626 5.563 ;
     RECT  42.768 5.503 42.786 5.639 ;
     RECT  46.98 5.563 49.626 5.639 ;
     RECT  2.34 5.495 7.002 5.765 ;
     RECT  47.88 5.639 49.626 5.999 ;
     RECT  48.132 5.999 49.626 6.269 ;
     RECT  48.132 6.269 48.474 6.413 ;
     RECT  48.456 6.413 48.474 6.539 ;
     RECT  49.212 6.269 49.626 6.611 ;
     RECT  2.415 5.765 3.186 28.651 ;
     RECT  3.96 5.765 7.002 28.651 ;
     RECT  12.096 5.189 26.226 36.931 ;
     RECT  12.096 36.931 26.55 37.037 ;
     RECT  7.815 4.919 10.422 41.647 ;
     RECT  7.815 41.647 10.854 41.909 ;
     RECT  12.096 37.037 26.226 43.141 ;
     RECT  7.815 41.909 10.422 43.375 ;
     RECT  7.815 43.375 10.494 43.411 ;
     RECT  7.815 43.411 11.106 43.501 ;
     RECT  7.815 43.501 11.25 43.573 ;
     RECT  7.815 43.573 11.322 43.601 ;
     RECT  11.052 43.601 11.322 43.613 ;
     RECT  12.096 43.141 26.514 43.673 ;
     RECT  11.052 43.613 11.25 43.799 ;
     RECT  29.415 2.413 29.697 44.185 ;
     RECT  2.415 28.651 7.002 44.419 ;
     RECT  7.815 43.601 10.278 44.419 ;
     RECT  2.415 44.419 10.278 44.455 ;
     RECT  12.24 43.673 26.514 44.455 ;
     RECT  2.34 44.455 10.278 44.581 ;
     RECT  11.088 43.799 11.25 44.581 ;
     RECT  34.815 2.413 35.097 44.653 ;
     RECT  45.615 3.569 45.897 44.725 ;
     RECT  40.215 2.413 40.497 44.761 ;
     RECT  45.615 44.725 46.458 44.851 ;
     RECT  40.215 44.761 41.202 44.887 ;
     RECT  2.34 44.581 11.25 45.031 ;
     RECT  12.24 44.455 26.766 45.031 ;
     RECT  2.34 45.031 11.502 45.193 ;
     RECT  12.24 45.031 26.874 45.193 ;
     RECT  42.876 45.193 42.894 45.265 ;
     RECT  34.815 44.653 35.73 45.301 ;
     RECT  45.615 44.851 47.178 45.301 ;
     RECT  48.276 45.121 48.294 45.301 ;
     RECT  2.34 45.193 26.874 45.419 ;
     RECT  40.14 44.887 41.202 45.499 ;
     RECT  11.628 45.419 26.874 45.527 ;
     RECT  42.804 45.265 42.894 45.691 ;
     RECT  45.615 45.301 48.294 45.697 ;
     RECT  49.212 6.611 49.23 45.697 ;
     RECT  37.26 45.571 37.278 45.733 ;
     RECT  2.34 45.419 10.818 45.821 ;
     RECT  45.615 45.697 49.23 46.075 ;
     RECT  45.615 46.075 49.374 46.111 ;
     RECT  27.936 46.039 27.954 46.123 ;
     RECT  33.228 46.075 33.246 46.171 ;
     RECT  33.084 46.171 33.246 46.201 ;
     RECT  31.644 46.171 31.662 46.219 ;
     RECT  31.644 46.219 31.734 46.237 ;
     RECT  32.94 46.201 33.246 46.237 ;
     RECT  42.804 45.691 43.11 46.237 ;
     RECT  2.376 45.821 10.818 46.253 ;
     RECT  30.888 46.219 30.906 46.267 ;
     RECT  31.644 46.237 33.246 46.267 ;
     RECT  39.708 45.499 41.202 46.267 ;
     RECT  42.66 46.237 43.11 46.309 ;
     RECT  44.208 45.229 44.226 46.309 ;
     RECT  39.348 46.267 41.202 46.345 ;
     RECT  45.615 46.111 49.59 46.345 ;
     RECT  2.415 46.253 10.818 46.381 ;
     RECT  11.736 45.527 26.874 46.381 ;
     RECT  27.936 46.123 28.566 46.381 ;
     RECT  29.415 44.185 29.862 46.381 ;
     RECT  42.66 46.309 44.226 46.381 ;
     RECT  45.144 46.345 49.59 46.381 ;
     RECT  30.888 46.267 33.246 46.459 ;
     RECT  34.236 45.301 35.73 46.459 ;
     RECT  27.864 46.381 29.862 46.507 ;
     RECT  2.415 46.381 26.874 46.543 ;
     RECT  30.708 46.459 35.73 46.543 ;
     RECT  2.415 46.543 27.054 46.555 ;
     RECT  27.864 46.507 29.934 46.555 ;
     RECT  37.26 45.733 37.35 46.579 ;
     RECT  39.348 46.345 41.418 46.603 ;
     RECT  30.708 46.543 36.09 46.615 ;
     RECT  37.224 46.579 37.35 46.615 ;
     RECT  39.312 46.603 41.418 46.615 ;
     RECT  42.588 46.381 49.59 46.615 ;
     RECT  2.415 46.555 29.934 46.651 ;
     RECT  30.708 46.615 36.27 46.651 ;
     RECT  37.08 46.615 37.35 46.651 ;
     RECT  38.088 44.491 38.106 46.651 ;
     RECT  37.08 46.651 38.106 46.741 ;
     RECT  37.08 46.741 38.538 46.777 ;
     RECT  39.312 46.615 49.59 46.777 ;
     RECT  2.415 46.651 36.27 46.849 ;
     RECT  37.08 46.777 49.59 46.849 ;
     RECT  2.415 46.849 49.59 47.389 ;
     RECT  2.376 47.389 49.59 47.731 ;
     RECT  2.304 47.731 49.59 48.461 ;
     RECT  2.304 48.461 49.554 48.965 ;
     RECT  27.252 48.965 49.554 49.351 ;
     RECT  27.252 49.351 50.202 49.421 ;
     RECT  31.68 49.421 50.202 49.469 ;
     RECT  2.304 48.965 26.406 49.505 ;
     RECT  27.252 49.421 30.87 49.505 ;
     RECT  31.68 49.469 49.41 49.505 ;
     RECT  3.312 49.505 26.406 49.541 ;
     RECT  27.396 49.505 29.826 49.541 ;
     RECT  1.548 49.171 1.566 49.565 ;
     RECT  2.304 49.505 2.574 49.565 ;
     RECT  27.396 49.541 29.754 49.565 ;
     RECT  31.68 49.505 43.506 49.565 ;
     RECT  3.384 49.541 26.406 49.577 ;
     RECT  4.896 49.577 24.105 49.613 ;
     RECT  28.224 49.565 29.754 49.613 ;
     RECT  44.244 49.505 49.41 49.613 ;
     RECT  2.415 49.565 2.574 49.697 ;
     RECT  10.764 49.613 24.105 49.697 ;
     RECT  4.896 49.613 10.026 50.141 ;
     RECT  28.98 49.613 29.754 50.141 ;
     RECT  44.244 49.613 49.338 50.141 ;
     RECT  2.556 49.697 2.574 50.189 ;
     RECT  4.896 50.141 9.126 50.189 ;
     RECT  10.764 49.697 23.994 50.189 ;
     RECT  24.912 49.577 26.406 50.189 ;
     RECT  30.564 49.505 30.87 50.189 ;
     RECT  31.68 49.565 41.166 50.189 ;
     RECT  41.94 49.565 43.506 50.189 ;
     RECT  44.244 50.141 48.078 50.189 ;
     RECT  48.924 50.141 48.942 50.189 ;
     RECT  3.384 49.577 3.834 50.669 ;
     RECT  3.384 50.669 3.402 50.717 ;
     RECT  4.896 50.189 5.13 50.717 ;
     RECT  6.552 50.189 7.29 50.717 ;
     RECT  8.028 50.189 9.126 50.717 ;
     RECT  10.008 50.141 10.026 50.717 ;
     RECT  10.764 50.189 12.618 50.717 ;
     RECT  13.788 50.189 17.55 50.717 ;
     RECT  18.324 50.189 18.342 50.717 ;
     RECT  19.152 50.189 21.006 50.717 ;
     RECT  22.86 50.189 23.994 50.717 ;
     RECT  26.388 50.189 26.406 50.717 ;
     RECT  27.396 49.565 27.414 50.717 ;
     RECT  28.224 49.613 28.242 50.717 ;
     RECT  29.736 50.141 29.754 50.717 ;
     RECT  30.852 50.189 30.87 50.717 ;
     RECT  31.68 50.189 32.886 50.717 ;
     RECT  33.912 50.189 34.65 50.717 ;
     RECT  35.82 50.189 37.026 50.717 ;
     RECT  38.16 50.189 39.258 50.717 ;
     RECT  40.752 50.189 40.77 50.717 ;
     RECT  41.94 50.189 42.282 50.717 ;
     RECT  43.128 50.189 43.146 50.717 ;
     RECT  44.964 50.189 48.078 50.717 ;
     RECT  34.632 50.717 34.65 50.765 ;
     RECT  36.144 50.717 36.162 50.765 ;
     RECT  42.264 50.717 42.282 50.765 ;
     RECT  48.06 50.717 48.078 50.765 ;
     RECT  50.184 49.469 50.202 50.765 ;
     RECT  31.68 50.717 31.698 51.725 ;
     RECT  45.54 50.717 45.558 51.725 ;
    LAYER M4 ;
     RECT  1.237 4.56 1.429 4.584 ;
     RECT  1.429 4.56 1.573 4.68 ;
     RECT  1.573 4.56 2.069 4.92 ;
     RECT  1.493 49.536 2.293 49.56 ;
     RECT  2.329 45.792 2.365 45.816 ;
     RECT  1.189 47.856 2.365 47.88 ;
     RECT  1.025 1.728 2.408 1.752 ;
     RECT  2.069 3.984 2.408 4.92 ;
     RECT  2.365 45.792 2.408 46.248 ;
     RECT  2.365 47.856 2.408 48.264 ;
     RECT  2.293 49.536 2.408 50.184 ;
     RECT  2.408 1.728 2.704 50.184 ;
     RECT  2.704 45.552 2.819 50.184 ;
     RECT  2.819 45.552 2.837 49.416 ;
     RECT  2.704 1.728 2.86 5.016 ;
     RECT  2.837 45.552 3.081 48.696 ;
     RECT  3.081 45.552 3.233 47.4 ;
     RECT  3.233 46.224 3.347 47.4 ;
     RECT  3.347 46.752 3.385 47.4 ;
     RECT  2.86 4.656 3.413 5.016 ;
     RECT  3.061 50.64 3.413 50.712 ;
     RECT  3.413 4.656 3.521 4.872 ;
     RECT  2.86 1.728 3.737 3.432 ;
     RECT  3.081 48.48 3.829 48.696 ;
     RECT  3.413 50.64 3.845 50.664 ;
     RECT  3.385 46.896 3.881 47.4 ;
     RECT  3.829 48.48 4.025 49.464 ;
     RECT  4.025 49.44 4.213 49.464 ;
     RECT  3.881 46.896 4.241 47.352 ;
     RECT  4.213 49.44 4.241 49.512 ;
     RECT  4.241 49.488 4.529 49.512 ;
     RECT  4.241 46.896 4.745 47.064 ;
     RECT  4.597 50.688 5.141 50.712 ;
     RECT  4.745 47.04 5.425 47.064 ;
     RECT  3.737 3.168 5.609 3.432 ;
     RECT  3.737 1.728 5.66 1.848 ;
     RECT  5.609 3.168 5.66 3.192 ;
     RECT  5.66 1.728 5.747 3.192 ;
     RECT  3.521 4.848 5.965 4.872 ;
     RECT  5.425 47.04 5.965 47.88 ;
     RECT  5.965 4.848 6.005 5.208 ;
     RECT  5.965 47.04 6.217 48.024 ;
     RECT  5.365 50.16 6.22 50.184 ;
     RECT  6.217 47.04 6.829 48.504 ;
     RECT  5.747 1.728 7.081 1.752 ;
     RECT  7.081 1.728 7.621 1.848 ;
     RECT  6.497 50.688 7.621 50.712 ;
     RECT  7.621 50.16 7.769 50.712 ;
     RECT  7.621 1.728 7.808 2.04 ;
     RECT  5.747 3.168 7.808 3.192 ;
     RECT  6.005 5.184 7.808 5.208 ;
     RECT  6.829 46.224 7.808 48.504 ;
     RECT  7.808 1.728 7.912 49.692 ;
     RECT  7.945 0.096 8.029 0.12 ;
     RECT  7.912 1.728 8.104 49.422 ;
     RECT  8.104 1.728 8.489 1.896 ;
     RECT  8.104 3.024 9.281 3.432 ;
     RECT  8.104 46.752 9.497 49.032 ;
     RECT  7.769 50.688 9.529 50.712 ;
     RECT  9.497 47.04 9.589 49.032 ;
     RECT  9.529 50.112 9.589 50.712 ;
     RECT  8.489 1.728 9.601 1.8 ;
     RECT  9.589 47.04 9.613 50.712 ;
     RECT  9.613 47.04 9.635 49.608 ;
     RECT  9.635 47.28 9.677 49.608 ;
     RECT  9.601 1.728 9.685 1.896 ;
     RECT  9.637 44.928 9.965 44.952 ;
     RECT  9.677 47.28 9.965 47.928 ;
     RECT  9.281 3.024 10.397 3.048 ;
     RECT  9.677 49.008 10.469 49.608 ;
     RECT  10.469 49.008 10.717 49.368 ;
     RECT  8.104 5.184 10.789 5.208 ;
     RECT  9.685 1.728 10.969 1.848 ;
     RECT  10.825 45.168 10.973 45.192 ;
     RECT  10.969 1.728 11.267 2.28 ;
     RECT  11.041 3.408 11.473 3.432 ;
     RECT  10.789 4.56 11.477 5.208 ;
     RECT  10.609 46.752 11.621 46.776 ;
     RECT  11.267 1.728 11.765 1.8 ;
     RECT  11.473 3.312 11.869 3.432 ;
     RECT  9.601 43.584 12.193 43.608 ;
     RECT  11.869 3.312 12.197 3.72 ;
     RECT  12.193 43.392 12.265 43.656 ;
     RECT  9.613 50.688 12.629 50.712 ;
     RECT  11.765 1.728 12.901 1.752 ;
     RECT  10.717 48.432 12.908 49.368 ;
     RECT  12.661 47.328 12.913 47.352 ;
     RECT  12.901 1.728 13.208 1.8 ;
     RECT  12.197 3.696 13.208 3.72 ;
     RECT  11.477 5.184 13.208 5.208 ;
     RECT  12.265 43.344 13.208 43.656 ;
     RECT  12.913 46.512 13.208 47.352 ;
     RECT  12.908 48.432 13.208 50.184 ;
     RECT  13.208 1.728 13.493 50.184 ;
     RECT  13.493 1.728 13.504 49.422 ;
     RECT  13.504 1.728 13.601 1.992 ;
     RECT  13.504 46.368 13.763 49.224 ;
     RECT  13.763 46.368 13.789 47.88 ;
     RECT  13.789 47.712 13.961 47.88 ;
     RECT  13.504 43.152 14.069 45.144 ;
     RECT  13.601 1.728 14.185 1.896 ;
     RECT  13.504 41.664 14.357 41.784 ;
     RECT  14.357 41.664 14.501 41.688 ;
     RECT  14.069 43.344 14.641 45.144 ;
     RECT  13.789 46.368 14.641 46.536 ;
     RECT  14.641 43.344 14.861 46.536 ;
     RECT  14.861 44.784 14.924 46.536 ;
     RECT  13.961 47.856 14.924 47.88 ;
     RECT  13.504 5.184 15.109 5.208 ;
     RECT  14.861 43.344 15.361 43.704 ;
     RECT  14.924 44.784 15.361 47.88 ;
     RECT  13.763 49.2 15.361 49.224 ;
     RECT  14.785 2.832 15.617 2.856 ;
     RECT  15.361 44.784 15.761 49.224 ;
     RECT  15.761 45.936 15.797 49.224 ;
     RECT  14.185 1.728 15.829 1.848 ;
     RECT  15.829 1.728 16.067 1.896 ;
     RECT  15.109 4.608 16.157 5.208 ;
     RECT  15.797 45.936 16.553 47.88 ;
     RECT  15.761 44.784 16.729 44.808 ;
     RECT  16.729 44.784 16.765 44.856 ;
     RECT  15.361 43.104 16.909 43.704 ;
     RECT  16.765 44.688 16.909 44.856 ;
     RECT  16.765 4.128 16.981 4.152 ;
     RECT  16.909 43.104 17.057 44.856 ;
     RECT  17.057 43.104 17.093 44.808 ;
     RECT  15.797 49.2 17.125 49.224 ;
     RECT  13.717 50.688 17.125 50.712 ;
     RECT  16.981 3.408 17.129 4.152 ;
     RECT  17.093 43.296 17.165 44.808 ;
     RECT  16.067 1.728 17.269 1.8 ;
     RECT  16.553 46.176 17.341 47.88 ;
     RECT  17.125 49.2 17.341 50.712 ;
     RECT  17.269 1.728 17.459 2.28 ;
     RECT  17.165 44.64 17.525 44.808 ;
     RECT  17.165 43.296 18.133 43.656 ;
     RECT  17.525 44.64 18.133 44.664 ;
     RECT  17.341 46.176 18.313 50.712 ;
     RECT  18.313 45.984 18.349 50.712 ;
     RECT  17.459 1.728 18.565 1.8 ;
     RECT  18.133 43.296 18.601 44.664 ;
     RECT  18.565 1.728 18.608 2.04 ;
     RECT  16.157 5.184 18.608 5.208 ;
     RECT  17.305 41.904 18.608 41.928 ;
     RECT  18.601 43.296 18.608 44.712 ;
     RECT  18.349 45.696 18.608 50.712 ;
     RECT  18.608 1.728 18.785 50.712 ;
     RECT  18.785 1.728 18.904 49.422 ;
     RECT  18.904 4.512 19.145 5.208 ;
     RECT  18.904 1.728 19.397 1.896 ;
     RECT  19.145 5.184 20.185 5.208 ;
     RECT  18.904 43.392 20.257 49.224 ;
     RECT  19.397 1.728 20.465 1.8 ;
     RECT  20.257 43.008 20.473 49.224 ;
     RECT  20.473 43.008 20.545 49.368 ;
     RECT  20.465 1.728 20.549 2.28 ;
     RECT  20.545 42.864 20.581 49.368 ;
     RECT  18.785 50.688 20.581 50.712 ;
     RECT  20.185 4.656 21.017 5.208 ;
     RECT  20.581 42.864 21.017 50.712 ;
     RECT  21.017 43.392 21.485 50.184 ;
     RECT  21.485 46.08 21.521 50.184 ;
     RECT  21.521 46.272 21.629 50.184 ;
     RECT  21.485 43.392 22.277 44.952 ;
     RECT  21.629 46.32 22.537 50.184 ;
     RECT  22.277 43.536 22.669 44.952 ;
     RECT  22.537 46.32 22.669 49.368 ;
     RECT  20.549 1.728 23.077 1.8 ;
     RECT  21.805 3.936 23.101 3.96 ;
     RECT  23.077 1.728 23.209 1.848 ;
     RECT  21.017 5.184 23.42 5.208 ;
     RECT  22.561 17.904 23.461 17.928 ;
     RECT  22.669 43.536 23.605 49.368 ;
     RECT  22.805 50.688 23.605 50.712 ;
     RECT  23.605 43.536 23.753 50.712 ;
     RECT  23.209 1.728 24.008 1.896 ;
     RECT  23.101 3.408 24.008 3.96 ;
     RECT  23.42 5.136 24.008 5.208 ;
     RECT  23.461 17.664 24.008 17.928 ;
     RECT  23.753 43.536 24.008 49.692 ;
     RECT  23.753 50.688 24.049 50.712 ;
     RECT  24.008 1.728 24.304 49.692 ;
     RECT  24.304 1.728 24.473 1.848 ;
     RECT  24.304 44.496 24.757 49.692 ;
     RECT  24.473 1.728 24.941 1.8 ;
     RECT  24.757 44.496 25.049 50.184 ;
     RECT  24.304 3.552 25.121 3.96 ;
     RECT  24.941 1.728 25.229 1.752 ;
     RECT  24.304 17.904 25.379 17.928 ;
     RECT  25.333 25.68 25.429 25.8 ;
     RECT  25.429 25.68 25.475 25.992 ;
     RECT  25.405 36.48 25.489 36.504 ;
     RECT  25.049 45.12 25.661 50.184 ;
     RECT  25.475 25.776 25.697 25.992 ;
     RECT  25.661 50.16 25.955 50.184 ;
     RECT  25.333 43.824 26.093 43.848 ;
     RECT  26.293 50.688 26.417 50.712 ;
     RECT  25.661 45.12 26.489 49.032 ;
     RECT  26.521 37.008 26.605 37.032 ;
     RECT  26.489 45.696 27.385 49.032 ;
     RECT  27.385 45.696 27.781 49.08 ;
     RECT  27.781 45.696 28.001 49.56 ;
     RECT  27.385 50.688 28.253 50.712 ;
     RECT  28.001 48.768 28.501 49.56 ;
     RECT  28.501 48.768 28.925 49.608 ;
     RECT  28.001 45.696 28.988 47.736 ;
     RECT  28.925 48.768 28.988 50.136 ;
     RECT  28.988 45.696 29.369 50.136 ;
     RECT  25.121 3.552 29.408 3.576 ;
     RECT  25.697 25.776 29.408 25.8 ;
     RECT  29.369 45.696 29.408 49.692 ;
     RECT  29.408 2.148 29.512 49.692 ;
     RECT  29.512 2.418 29.704 49.692 ;
     RECT  29.681 50.688 29.765 50.712 ;
     RECT  30.469 50.16 30.593 50.184 ;
     RECT  30.841 50.688 30.925 50.712 ;
     RECT  29.704 45.696 31.205 49.032 ;
     RECT  31.205 48.528 31.237 49.032 ;
     RECT  31.237 48.528 31.349 49.416 ;
     RECT  31.621 51.696 31.709 51.72 ;
     RECT  31.205 45.696 32.209 47.064 ;
     RECT  31.349 48.528 32.209 49.032 ;
     RECT  31.993 50.688 33.109 50.712 ;
     RECT  33.109 50.16 33.539 50.712 ;
     RECT  32.209 45.696 33.685 49.032 ;
     RECT  33.539 50.688 34.604 50.712 ;
     RECT  34.604 50.688 34.691 50.76 ;
     RECT  29.704 3.552 34.808 3.576 ;
     RECT  29.704 25.776 34.808 25.8 ;
     RECT  33.685 45.696 34.808 49.224 ;
     RECT  34.808 2.148 34.912 49.692 ;
     RECT  34.912 2.418 35.029 49.692 ;
     RECT  35.029 2.418 35.104 50.184 ;
     RECT  35.104 45.696 35.459 50.184 ;
     RECT  35.765 50.688 36.133 50.712 ;
     RECT  36.133 50.688 36.227 50.76 ;
     RECT  36.227 50.688 37.037 50.712 ;
     RECT  35.459 45.696 37.333 49.224 ;
     RECT  37.333 45.696 37.469 50.184 ;
     RECT  37.469 45.696 37.793 49.224 ;
     RECT  37.793 48.72 38.045 49.224 ;
     RECT  37.793 45.696 38.945 47.736 ;
     RECT  38.053 50.688 39.269 50.712 ;
     RECT  38.045 48.96 39.349 49.224 ;
     RECT  39.349 48.432 39.589 49.224 ;
     RECT  35.104 3.552 40.208 3.576 ;
     RECT  35.104 25.776 40.208 25.8 ;
     RECT  38.945 45.696 40.208 47.4 ;
     RECT  39.589 48.432 40.208 50.184 ;
     RECT  40.208 2.148 40.312 50.184 ;
     RECT  40.312 2.418 40.504 50.184 ;
     RECT  40.504 48.96 40.741 50.184 ;
     RECT  40.741 48.96 40.825 50.712 ;
     RECT  40.825 48.96 41.177 50.184 ;
     RECT  41.177 49.2 41.212 50.184 ;
     RECT  40.504 45.696 41.605 46.92 ;
     RECT  41.212 49.2 41.609 49.56 ;
     RECT  41.605 45.696 41.821 47.4 ;
     RECT  41.821 45.696 42.217 47.496 ;
     RECT  41.885 50.688 42.236 50.712 ;
     RECT  42.236 50.688 42.323 50.76 ;
     RECT  42.217 45.696 42.613 47.832 ;
     RECT  41.609 49.2 42.613 49.224 ;
     RECT  42.613 45.696 42.62 49.224 ;
     RECT  42.323 50.688 42.62 50.712 ;
     RECT  40.504 3.552 42.757 3.576 ;
     RECT  42.757 3.552 42.797 3.672 ;
     RECT  42.62 45.696 43.121 50.712 ;
     RECT  43.121 46.512 43.157 50.712 ;
     RECT  43.157 46.512 43.661 50.184 ;
     RECT  43.661 46.656 43.733 50.184 ;
     RECT  43.733 46.656 44.579 46.92 ;
     RECT  43.733 47.904 44.705 50.184 ;
     RECT  44.579 46.8 44.917 46.92 ;
     RECT  44.705 47.904 44.917 49.692 ;
     RECT  44.909 50.688 44.993 50.712 ;
     RECT  45.301 51.696 45.569 51.72 ;
     RECT  42.797 3.648 45.608 3.672 ;
     RECT  40.504 25.776 45.608 25.8 ;
     RECT  44.917 46.8 45.608 49.692 ;
     RECT  45.608 2.148 45.685 49.692 ;
     RECT  45.685 2.148 45.712 50.424 ;
     RECT  45.712 50.4 45.785 50.424 ;
     RECT  45.712 2.418 45.904 49.422 ;
     RECT  45.904 46.896 46.037 49.224 ;
     RECT  46.037 49.2 46.289 49.224 ;
     RECT  20.005 0.048 46.933 0.072 ;
     RECT  46.037 46.896 47.113 47.928 ;
     RECT  45.904 2.784 47.183 3.672 ;
     RECT  46.969 5.568 47.225 5.592 ;
     RECT  47.183 2.784 47.405 3.96 ;
     RECT  46.933 0.048 47.437 0.12 ;
     RECT  47.317 1.728 47.473 1.752 ;
     RECT  47.113 46.896 47.509 48.408 ;
     RECT  47.405 3.648 47.801 3.96 ;
     RECT  47.509 46.896 47.977 48.648 ;
     RECT  46.069 50.688 48.016 50.712 ;
     RECT  47.977 46.896 48.053 49.368 ;
     RECT  47.473 1.728 48.179 2.28 ;
     RECT  48.053 47.136 48.325 49.368 ;
     RECT  48.016 50.688 48.325 50.76 ;
     RECT  47.437 0.048 48.373 0.6 ;
     RECT  48.229 5.04 48.629 5.064 ;
     RECT  48.325 47.136 48.755 50.76 ;
     RECT  45.904 25.776 48.899 25.8 ;
     RECT  48.755 47.136 48.989 50.184 ;
     RECT  47.801 3.936 49.061 3.96 ;
     RECT  48.989 47.136 49.061 48.216 ;
     RECT  48.373 0.048 49.139 0.696 ;
     RECT  48.989 49.344 49.139 50.184 ;
     RECT  49.189 3.408 49.313 3.432 ;
     RECT  48.179 2.256 49.345 2.28 ;
     RECT  49.345 2.256 49.378 2.856 ;
     RECT  49.139 49.344 49.385 50.136 ;
     RECT  49.061 48 49.493 48.024 ;
     RECT  49.385 49.584 49.523 50.136 ;
     RECT  49.378 2.208 49.571 2.856 ;
     RECT  49.139 0.432 49.597 0.696 ;
     RECT  49.597 0.432 49.676 1.128 ;
     RECT  49.676 0.432 49.763 1.704 ;
     RECT  49.523 49.632 49.907 50.136 ;
     RECT  49.763 0.432 49.997 1.128 ;
     RECT  49.997 0.48 50.099 1.128 ;
     RECT  49.907 50.112 50.173 50.136 ;
     RECT  49.571 2.832 50.243 2.856 ;
     RECT  50.173 50.112 50.291 50.76 ;
     RECT  50.099 0.48 50.435 0.696 ;
     RECT  50.435 0.528 50.627 0.696 ;
     RECT  50.291 50.736 50.675 50.76 ;
     RECT  50.627 0.528 50.771 0.552 ;
    LAYER M5 ;
     RECT  47.352 0.016 47.472 0.084 ;
     RECT  47.496 0.016 47.664 0.084 ;
     RECT  47.688 0.016 47.808 0.084 ;
     RECT  47.832 0.016 48 0.084 ;
     RECT  48.024 0.016 48.144 0.084 ;
     RECT  48.168 0.016 48.336 0.084 ;
     RECT  48.36 0.016 48.528 0.084 ;
     RECT  48.552 0.016 48.672 0.084 ;
     RECT  48.696 0.016 48.864 0.084 ;
     RECT  48.888 0.016 49.008 0.084 ;
     RECT  49.032 0.016 49.2 0.084 ;
     RECT  49.224 0.016 49.344 0.084 ;
     RECT  49.368 0.016 49.536 0.084 ;
     RECT  49.56 0.016 49.728 0.084 ;
     RECT  49.752 0.016 49.872 0.084 ;
     RECT  49.896 0.016 50.064 0.084 ;
     RECT  50.088 0.016 50.208 0.084 ;
     RECT  50.232 0.016 50.4 0.084 ;
     RECT  50.424 0.016 50.592 0.084 ;
     RECT  50.616 0.016 50.736 0.084 ;
     RECT  47.328 0.084 50.76 0.563 ;
     RECT  47.328 0.563 50.616 0.707 ;
     RECT  1.08 0.016 1.248 0.084 ;
     RECT  1.272 0.016 1.44 0.084 ;
     RECT  1.464 0.016 1.584 0.084 ;
     RECT  1.608 0.016 1.776 0.084 ;
     RECT  1.8 0.016 1.92 0.084 ;
     RECT  1.944 0.016 2.112 0.084 ;
     RECT  2.136 0.016 2.256 0.084 ;
     RECT  2.28 0.016 2.448 0.084 ;
     RECT  2.472 0.016 2.64 0.084 ;
     RECT  2.664 0.016 2.784 0.084 ;
     RECT  2.808 0.016 2.976 0.084 ;
     RECT  3 0.016 3.12 0.084 ;
     RECT  3.144 0.016 3.312 0.084 ;
     RECT  3.336 0.016 3.504 0.084 ;
     RECT  3.528 0.016 3.648 0.084 ;
     RECT  3.672 0.016 3.84 0.084 ;
     RECT  3.864 0.016 3.984 0.084 ;
     RECT  4.008 0.016 4.176 0.084 ;
     RECT  4.2 0.016 4.32 0.084 ;
     RECT  4.344 0.016 4.512 0.084 ;
     RECT  4.536 0.016 4.704 0.084 ;
     RECT  4.728 0.016 4.848 0.084 ;
     RECT  4.872 0.016 5.04 0.084 ;
     RECT  5.064 0.016 5.184 0.084 ;
     RECT  5.208 0.016 5.376 0.084 ;
     RECT  5.4 0.016 5.52 0.084 ;
     RECT  5.544 0.016 5.712 0.084 ;
     RECT  5.736 0.016 5.904 0.084 ;
     RECT  5.928 0.016 6.048 0.084 ;
     RECT  6.072 0.016 6.24 0.084 ;
     RECT  6.264 0.016 6.384 0.084 ;
     RECT  6.408 0.016 6.576 0.084 ;
     RECT  6.6 0.016 6.768 0.084 ;
     RECT  6.792 0.016 6.912 0.084 ;
     RECT  6.936 0.016 7.104 0.084 ;
     RECT  7.128 0.016 7.248 0.084 ;
     RECT  7.272 0.016 7.44 0.084 ;
     RECT  7.464 0.016 7.584 0.084 ;
     RECT  7.608 0.016 7.776 0.084 ;
     RECT  7.8 0.016 7.968 0.084 ;
     RECT  7.992 0.016 8.112 0.084 ;
     RECT  8.136 0.016 8.304 0.084 ;
     RECT  8.328 0.016 8.448 0.084 ;
     RECT  8.472 0.016 8.64 0.084 ;
     RECT  8.664 0.016 8.832 0.084 ;
     RECT  8.856 0.016 8.976 0.084 ;
     RECT  9 0.016 9.168 0.084 ;
     RECT  9.192 0.016 9.312 0.084 ;
     RECT  9.336 0.016 9.504 0.084 ;
     RECT  9.528 0.016 9.648 0.084 ;
     RECT  9.672 0.016 9.84 0.084 ;
     RECT  9.864 0.016 10.032 0.084 ;
     RECT  10.056 0.016 10.176 0.084 ;
     RECT  10.2 0.016 10.368 0.084 ;
     RECT  10.392 0.016 10.512 0.084 ;
     RECT  10.536 0.016 10.704 0.084 ;
     RECT  10.728 0.016 10.848 0.084 ;
     RECT  10.872 0.016 11.04 0.084 ;
     RECT  11.064 0.016 11.232 0.084 ;
     RECT  11.256 0.016 11.376 0.084 ;
     RECT  11.4 0.016 11.568 0.084 ;
     RECT  11.592 0.016 11.712 0.084 ;
     RECT  11.736 0.016 11.904 0.084 ;
     RECT  11.928 0.016 12.096 0.084 ;
     RECT  12.12 0.016 12.24 0.084 ;
     RECT  12.264 0.016 12.432 0.084 ;
     RECT  12.456 0.016 12.576 0.084 ;
     RECT  12.6 0.016 12.768 0.084 ;
     RECT  12.792 0.016 12.912 0.084 ;
     RECT  12.936 0.016 13.104 0.084 ;
     RECT  13.128 0.016 13.296 0.084 ;
     RECT  13.32 0.016 13.44 0.084 ;
     RECT  13.464 0.016 13.632 0.084 ;
     RECT  13.656 0.016 13.776 0.084 ;
     RECT  13.8 0.016 13.968 0.084 ;
     RECT  13.992 0.016 14.112 0.084 ;
     RECT  14.136 0.016 14.304 0.084 ;
     RECT  14.328 0.016 14.496 0.084 ;
     RECT  14.52 0.016 14.64 0.084 ;
     RECT  14.664 0.016 14.832 0.084 ;
     RECT  14.856 0.016 14.976 0.084 ;
     RECT  15 0.016 15.168 0.084 ;
     RECT  15.192 0.016 15.36 0.084 ;
     RECT  15.384 0.016 15.504 0.084 ;
     RECT  15.528 0.016 15.696 0.084 ;
     RECT  15.72 0.016 15.84 0.084 ;
     RECT  15.864 0.016 16.032 0.084 ;
     RECT  16.056 0.016 16.176 0.084 ;
     RECT  16.2 0.016 16.368 0.084 ;
     RECT  16.392 0.016 16.56 0.084 ;
     RECT  16.584 0.016 16.704 0.084 ;
     RECT  16.728 0.016 16.896 0.084 ;
     RECT  16.92 0.016 17.04 0.084 ;
     RECT  17.064 0.016 17.232 0.084 ;
     RECT  17.256 0.016 17.424 0.084 ;
     RECT  17.448 0.016 17.568 0.084 ;
     RECT  17.592 0.016 17.76 0.084 ;
     RECT  17.784 0.016 17.904 0.084 ;
     RECT  17.928 0.016 18.096 0.084 ;
     RECT  18.12 0.016 18.24 0.084 ;
     RECT  18.264 0.016 18.432 0.084 ;
     RECT  18.456 0.016 18.624 0.084 ;
     RECT  18.648 0.016 18.768 0.084 ;
     RECT  18.792 0.016 18.96 0.084 ;
     RECT  18.984 0.016 19.104 0.084 ;
     RECT  19.128 0.016 19.296 0.084 ;
     RECT  19.32 0.016 19.44 0.084 ;
     RECT  19.464 0.016 19.632 0.084 ;
     RECT  19.656 0.016 19.824 0.084 ;
     RECT  19.848 0.016 19.968 0.084 ;
     RECT  19.992 0.016 20.16 0.084 ;
     RECT  20.184 0.016 20.304 0.084 ;
     RECT  20.328 0.016 20.496 0.084 ;
     RECT  20.52 0.016 20.688 0.084 ;
     RECT  20.712 0.016 20.832 0.084 ;
     RECT  20.856 0.016 21.024 0.084 ;
     RECT  21.048 0.016 21.168 0.084 ;
     RECT  21.192 0.016 21.36 0.084 ;
     RECT  21.384 0.016 21.504 0.084 ;
     RECT  21.528 0.016 21.696 0.084 ;
     RECT  21.72 0.016 21.888 0.084 ;
     RECT  21.912 0.016 22.032 0.084 ;
     RECT  22.056 0.016 22.224 0.084 ;
     RECT  22.248 0.016 22.368 0.084 ;
     RECT  22.392 0.016 22.56 0.084 ;
     RECT  22.584 0.016 22.752 0.084 ;
     RECT  22.776 0.016 22.896 0.084 ;
     RECT  22.92 0.016 23.088 0.084 ;
     RECT  23.112 0.016 23.232 0.084 ;
     RECT  23.256 0.016 23.424 0.084 ;
     RECT  23.448 0.016 23.568 0.084 ;
     RECT  23.592 0.016 23.76 0.084 ;
     RECT  23.784 0.016 23.952 0.084 ;
     RECT  23.976 0.016 24.096 0.084 ;
     RECT  24.12 0.016 24.288 0.084 ;
     RECT  24.312 0.016 24.432 0.084 ;
     RECT  24.456 0.016 24.624 0.084 ;
     RECT  24.648 0.016 24.768 0.084 ;
     RECT  24.792 0.016 24.96 0.084 ;
     RECT  24.984 0.016 25.152 0.084 ;
     RECT  1.056 0.084 25.176 1.763 ;
     RECT  47.328 0.707 50.232 1.763 ;
     RECT  7.104 1.763 11.736 1.811 ;
     RECT  12.912 1.763 24.792 1.811 ;
     RECT  1.248 1.763 5.736 1.859 ;
     RECT  7.104 1.811 8.472 1.859 ;
     RECT  9.648 1.811 11.256 1.859 ;
     RECT  15.168 1.811 16.056 1.859 ;
     RECT  23.088 1.811 24.456 1.859 ;
     RECT  7.776 1.859 8.472 1.907 ;
     RECT  9.648 1.859 9.672 1.907 ;
     RECT  13.2 1.811 14.136 1.907 ;
     RECT  16.032 1.859 16.056 1.907 ;
     RECT  18.6 1.811 19.32 1.907 ;
     RECT  23.232 1.859 24.312 1.907 ;
     RECT  7.776 1.907 8.112 2.051 ;
     RECT  29.4 2.137 29.52 2.151 ;
     RECT  34.8 2.137 34.92 2.151 ;
     RECT  40.2 2.137 40.32 2.151 ;
     RECT  45.6 2.137 45.72 2.151 ;
     RECT  1.248 1.859 3.672 2.291 ;
     RECT  5.712 1.859 5.736 2.291 ;
     RECT  11.232 1.859 11.256 2.291 ;
     RECT  17.424 1.811 17.448 2.291 ;
     RECT  20.496 1.811 20.52 2.291 ;
     RECT  47.664 1.763 50.232 2.291 ;
     RECT  50.208 2.291 50.232 2.867 ;
     RECT  48.864 2.291 49.224 3.443 ;
     RECT  24 1.907 24.312 3.637 ;
     RECT  47.232 2.773 47.256 3.971 ;
     RECT  1.248 2.291 2.808 4.019 ;
     RECT  1.248 4.019 2.712 4.595 ;
     RECT  1.44 4.595 2.712 4.691 ;
     RECT  1.584 4.691 2.712 4.931 ;
     RECT  23.472 3.637 24.312 17.699 ;
     RECT  25.344 17.893 25.368 25.669 ;
     RECT  25.344 25.669 25.464 25.715 ;
     RECT  48.864 3.443 48.888 25.811 ;
     RECT  25.44 25.715 25.464 36.515 ;
     RECT  18.6 1.907 18.912 43.285 ;
     RECT  2.4 4.931 2.712 45.541 ;
     RECT  2.4 45.541 3.144 46.213 ;
     RECT  33.168 46.261 33.192 46.451 ;
     RECT  24 17.699 24.312 46.453 ;
     RECT  23.904 46.453 24.312 46.595 ;
     RECT  40.2 2.151 40.512 46.597 ;
     RECT  2.4 46.213 3.336 46.787 ;
     RECT  30.768 46.645 30.792 46.787 ;
     RECT  24 46.595 24.312 46.789 ;
     RECT  24 46.789 24.408 46.885 ;
     RECT  24 46.885 24.6 47.075 ;
     RECT  13.2 1.907 13.512 47.269 ;
     RECT  39.36 46.597 40.512 47.411 ;
     RECT  36.432 46.645 36.456 47.651 ;
     RECT  17.904 43.285 18.912 47.699 ;
     RECT  2.4 46.787 3.048 47.843 ;
     RECT  14.976 46.885 15 47.891 ;
     RECT  24 47.075 24.408 47.891 ;
     RECT  9.6 47.029 9.624 47.893 ;
     RECT  32.832 46.645 32.856 47.939 ;
     RECT  26.544 36.997 26.568 48.421 ;
     RECT  29.4 2.151 29.712 48.421 ;
     RECT  40.2 47.411 40.512 48.421 ;
     RECT  20.592 47.845 20.616 48.467 ;
     RECT  26.544 48.421 26.712 48.517 ;
     RECT  2.4 47.843 2.904 48.707 ;
     RECT  9.216 47.893 9.624 48.803 ;
     RECT  13.2 47.269 13.752 48.899 ;
     RECT  43.008 47.893 43.032 48.899 ;
     RECT  44.544 46.645 44.568 48.899 ;
     RECT  39.36 48.421 40.512 48.995 ;
     RECT  26.544 48.517 27.096 49.043 ;
     RECT  33.696 48.277 33.72 49.235 ;
     RECT  3.84 49.429 3.864 49.477 ;
     RECT  1.2 47.845 1.224 49.525 ;
     RECT  2.4 48.707 2.808 49.525 ;
     RECT  24 47.891 24.312 49.525 ;
     RECT  26.688 49.043 27.096 49.525 ;
     RECT  9.6 48.803 9.624 49.573 ;
     RECT  26.688 49.525 27.816 49.573 ;
     RECT  29.04 48.421 30.12 49.573 ;
     RECT  49.488 49.573 49.512 49.621 ;
     RECT  7.8 2.051 8.112 49.689 ;
     RECT  13.2 48.899 13.512 49.689 ;
     RECT  18.6 47.699 18.912 49.689 ;
     RECT  45.6 2.151 45.912 49.689 ;
     RECT  7.8 49.689 7.92 49.703 ;
     RECT  18.6 49.689 18.72 49.703 ;
     RECT  34.8 2.151 35.112 49.703 ;
     RECT  45.6 49.689 45.72 49.703 ;
     RECT  9.6 49.573 10.344 50.101 ;
     RECT  49.488 49.621 49.896 50.101 ;
     RECT  13.2 49.689 13.368 50.149 ;
     RECT  18.6 49.703 18.696 50.149 ;
     RECT  20.592 50.101 20.616 50.149 ;
     RECT  22.464 50.101 22.488 50.149 ;
     RECT  24 49.525 24.408 50.149 ;
     RECT  25.536 49.525 25.56 50.149 ;
     RECT  26.688 49.573 30.12 50.149 ;
     RECT  31.248 49.381 31.272 50.149 ;
     RECT  35.04 49.703 35.112 50.149 ;
     RECT  37.68 47.893 37.704 50.149 ;
     RECT  40.2 48.995 40.512 50.149 ;
     RECT  41.52 49.525 41.544 50.149 ;
     RECT  43.776 48.997 43.8 50.149 ;
     RECT  48.336 50.101 48.36 50.149 ;
     RECT  49.488 50.101 50.28 50.149 ;
     RECT  1.2 49.525 2.808 50.629 ;
     RECT  3.84 49.477 4.248 50.629 ;
     RECT  1.2 50.629 4.248 50.677 ;
     RECT  5.376 50.149 6.168 50.677 ;
     RECT  7.632 50.149 7.656 50.677 ;
     RECT  9.552 50.101 10.344 50.677 ;
     RECT  12.96 50.149 13.368 50.677 ;
     RECT  17.136 50.149 18.696 50.677 ;
     RECT  20.592 50.149 22.488 50.677 ;
     RECT  23.616 50.149 31.272 50.677 ;
     RECT  33.12 50.149 33.528 50.677 ;
     RECT  35.04 50.149 35.448 50.677 ;
     RECT  37.344 50.149 37.704 50.677 ;
     RECT  39.6 50.149 41.544 50.677 ;
     RECT  42.672 50.149 44.568 50.677 ;
     RECT  45.696 49.703 45.72 50.677 ;
     RECT  48.336 50.149 50.28 50.677 ;
     RECT  1.2 50.677 50.28 50.725 ;
     RECT  1.2 50.725 50.664 51.756 ;
     RECT  1.224 51.756 1.536 51.792 ;
     RECT  1.56 51.756 1.92 51.792 ;
     RECT  1.944 51.756 2.304 51.792 ;
     RECT  2.328 51.756 2.688 51.792 ;
     RECT  2.712 51.756 3.072 51.792 ;
     RECT  3.096 51.756 3.456 51.792 ;
     RECT  3.48 51.756 3.84 51.792 ;
     RECT  3.864 51.756 4.224 51.792 ;
     RECT  4.248 51.756 4.608 51.792 ;
     RECT  4.632 51.756 4.992 51.792 ;
     RECT  5.016 51.756 5.376 51.792 ;
     RECT  5.4 51.756 5.76 51.792 ;
     RECT  5.784 51.756 6.144 51.792 ;
     RECT  6.168 51.756 6.528 51.792 ;
     RECT  6.552 51.756 6.864 51.792 ;
     RECT  6.888 51.756 7.248 51.792 ;
     RECT  7.272 51.756 7.632 51.792 ;
     RECT  7.656 51.756 8.016 51.792 ;
     RECT  8.04 51.756 8.4 51.792 ;
     RECT  8.424 51.756 8.784 51.792 ;
     RECT  8.808 51.756 9.168 51.792 ;
     RECT  9.192 51.756 9.552 51.792 ;
     RECT  9.576 51.756 9.936 51.792 ;
     RECT  9.96 51.756 10.32 51.792 ;
     RECT  10.344 51.756 10.704 51.792 ;
     RECT  10.728 51.756 11.088 51.792 ;
     RECT  11.112 51.756 11.472 51.792 ;
     RECT  11.496 51.756 11.808 51.792 ;
     RECT  11.832 51.756 12.192 51.792 ;
     RECT  12.216 51.756 12.576 51.792 ;
     RECT  12.6 51.756 12.96 51.792 ;
     RECT  12.984 51.756 13.344 51.792 ;
     RECT  13.368 51.756 13.728 51.792 ;
     RECT  13.752 51.756 14.112 51.792 ;
     RECT  14.136 51.756 14.496 51.792 ;
     RECT  14.52 51.756 14.88 51.792 ;
     RECT  14.904 51.756 15.264 51.792 ;
     RECT  15.288 51.756 15.648 51.792 ;
     RECT  15.672 51.756 16.032 51.792 ;
     RECT  16.056 51.756 16.416 51.792 ;
     RECT  16.44 51.756 16.8 51.792 ;
     RECT  16.824 51.756 17.136 51.792 ;
     RECT  17.16 51.756 17.52 51.792 ;
     RECT  17.544 51.756 17.904 51.792 ;
     RECT  17.928 51.756 18.288 51.792 ;
     RECT  18.312 51.756 18.672 51.792 ;
     RECT  18.696 51.756 19.056 51.792 ;
     RECT  19.08 51.756 19.44 51.792 ;
     RECT  19.464 51.756 19.824 51.792 ;
     RECT  19.848 51.756 20.208 51.792 ;
     RECT  20.232 51.756 20.592 51.792 ;
     RECT  20.616 51.756 20.976 51.792 ;
     RECT  21 51.756 21.36 51.792 ;
     RECT  21.384 51.756 21.744 51.792 ;
     RECT  21.768 51.756 22.08 51.792 ;
     RECT  22.104 51.756 22.464 51.792 ;
     RECT  22.488 51.756 22.848 51.792 ;
     RECT  22.872 51.756 23.232 51.792 ;
     RECT  23.256 51.756 23.616 51.792 ;
     RECT  23.64 51.756 24 51.792 ;
     RECT  24.024 51.756 24.384 51.792 ;
     RECT  24.408 51.756 24.768 51.792 ;
     RECT  24.792 51.756 25.152 51.792 ;
     RECT  25.176 51.756 25.536 51.792 ;
     RECT  25.56 51.756 25.92 51.792 ;
     RECT  25.944 51.756 26.304 51.792 ;
     RECT  26.328 51.756 26.688 51.792 ;
     RECT  26.712 51.756 27.072 51.792 ;
     RECT  27.096 51.756 27.408 51.792 ;
     RECT  27.432 51.756 27.792 51.792 ;
     RECT  27.816 51.756 28.176 51.792 ;
     RECT  28.2 51.756 28.56 51.792 ;
     RECT  28.584 51.756 28.944 51.792 ;
     RECT  28.968 51.756 29.328 51.792 ;
     RECT  29.352 51.756 29.712 51.792 ;
     RECT  29.736 51.756 30.096 51.792 ;
     RECT  30.12 51.756 30.48 51.792 ;
     RECT  30.504 51.756 30.864 51.792 ;
     RECT  30.888 51.756 31.248 51.792 ;
     RECT  31.272 51.756 31.632 51.792 ;
     RECT  31.656 51.756 32.016 51.792 ;
     RECT  32.04 51.756 32.4 51.792 ;
     RECT  32.424 51.756 32.736 51.792 ;
     RECT  32.76 51.756 33.12 51.792 ;
     RECT  33.144 51.756 33.504 51.792 ;
     RECT  33.528 51.756 33.888 51.792 ;
     RECT  33.912 51.756 34.272 51.792 ;
     RECT  34.296 51.756 34.656 51.792 ;
     RECT  34.68 51.756 35.04 51.792 ;
     RECT  35.064 51.756 35.424 51.792 ;
     RECT  35.448 51.756 35.808 51.792 ;
     RECT  35.832 51.756 36.192 51.792 ;
     RECT  36.216 51.756 36.576 51.792 ;
     RECT  36.6 51.756 36.96 51.792 ;
     RECT  36.984 51.756 37.344 51.792 ;
     RECT  37.368 51.756 37.68 51.792 ;
     RECT  37.704 51.756 38.064 51.792 ;
     RECT  38.088 51.756 38.448 51.792 ;
     RECT  38.472 51.756 38.832 51.792 ;
     RECT  38.856 51.756 39.216 51.792 ;
     RECT  39.24 51.756 39.6 51.792 ;
     RECT  39.624 51.756 39.984 51.792 ;
     RECT  40.008 51.756 40.368 51.792 ;
     RECT  40.392 51.756 40.752 51.792 ;
     RECT  40.776 51.756 41.136 51.792 ;
     RECT  41.16 51.756 41.52 51.792 ;
     RECT  41.544 51.756 41.904 51.792 ;
     RECT  41.928 51.756 42.288 51.792 ;
     RECT  42.312 51.756 42.672 51.792 ;
     RECT  42.696 51.756 43.008 51.792 ;
     RECT  43.032 51.756 43.392 51.792 ;
     RECT  43.416 51.756 43.776 51.792 ;
     RECT  43.8 51.756 44.16 51.792 ;
     RECT  44.184 51.756 44.544 51.792 ;
     RECT  44.568 51.756 44.928 51.792 ;
     RECT  44.952 51.756 45.312 51.792 ;
     RECT  45.336 51.756 45.696 51.792 ;
     RECT  45.72 51.756 46.08 51.792 ;
     RECT  46.104 51.756 46.464 51.792 ;
     RECT  46.488 51.756 46.848 51.792 ;
     RECT  46.872 51.756 47.232 51.792 ;
     RECT  47.256 51.756 47.616 51.792 ;
     RECT  47.64 51.756 47.952 51.792 ;
     RECT  47.976 51.756 48.336 51.792 ;
     RECT  48.36 51.756 48.72 51.792 ;
     RECT  48.744 51.756 49.104 51.792 ;
     RECT  49.128 51.756 49.488 51.792 ;
     RECT  49.512 51.756 49.872 51.792 ;
     RECT  49.896 51.756 50.256 51.792 ;
     RECT  50.28 51.756 50.64 51.792 ;
     RECT  5.736 1.763 7.104 1.859 ;
     RECT  11.736 1.763 12.912 1.811 ;
     RECT  8.472 1.811 9.648 1.907 ;
     RECT  14.136 1.811 15.168 1.859 ;
     RECT  16.056 1.811 17.424 1.907 ;
     RECT  17.448 1.811 18.6 2.291 ;
     RECT  19.32 1.811 20.496 1.907 ;
     RECT  49.224 2.291 50.208 2.867 ;
     RECT  45.912 2.773 47.232 3.971 ;
     RECT  24.312 17.893 25.344 25.715 ;
     RECT  24.312 25.715 25.44 36.515 ;
     RECT  29.712 46.645 30.768 46.787 ;
     RECT  35.112 46.645 36.432 47.651 ;
     RECT  44.568 46.645 45.6 48.899 ;
     RECT  13.512 46.885 14.976 47.269 ;
     RECT  8.112 47.029 9.6 47.893 ;
     RECT  13.752 47.269 14.976 47.891 ;
     RECT  39.36 47.411 40.2 48.421 ;
     RECT  1.224 47.845 2.4 49.525 ;
     RECT  8.112 47.893 9.216 48.803 ;
     RECT  43.032 47.893 44.544 48.899 ;
     RECT  33.72 48.277 34.8 49.235 ;
     RECT  2.808 48.707 2.904 49.429 ;
     RECT  8.112 48.803 9.6 49.689 ;
     RECT  43.008 48.899 45.6 48.997 ;
     RECT  39.6 48.995 40.2 50.149 ;
     RECT  43.008 48.997 43.776 49.525 ;
     RECT  43.8 48.997 45.6 49.703 ;
     RECT  26.544 49.043 26.688 49.525 ;
     RECT  33.696 49.235 34.8 49.703 ;
     RECT  30.12 49.381 31.248 50.149 ;
     RECT  2.808 49.429 3.84 50.629 ;
     RECT  24.408 49.525 25.536 50.149 ;
     RECT  25.56 49.525 26.688 50.149 ;
     RECT  27.816 49.525 29.04 49.573 ;
     RECT  40.512 49.525 41.52 50.149 ;
     RECT  41.544 49.525 43.776 50.149 ;
     RECT  7.92 49.689 9.6 49.703 ;
     RECT  13.368 49.689 13.512 50.677 ;
     RECT  18.72 49.689 18.912 49.703 ;
     RECT  45.72 49.689 45.912 50.677 ;
     RECT  7.8 49.703 9.6 50.101 ;
     RECT  18.696 49.703 18.912 50.677 ;
     RECT  33.696 49.703 35.04 50.149 ;
     RECT  43.8 49.703 45.696 50.149 ;
     RECT  7.8 50.101 9.552 50.149 ;
     RECT  22.488 50.101 24 50.149 ;
     RECT  48.36 50.101 49.488 50.149 ;
     RECT  4.248 50.149 5.376 50.677 ;
     RECT  6.168 50.149 7.632 50.677 ;
     RECT  7.656 50.149 9.552 50.677 ;
     RECT  22.488 50.149 23.616 50.677 ;
     RECT  33.528 50.149 35.04 50.677 ;
     RECT  41.544 50.149 42.672 50.677 ;
     RECT  44.568 50.149 45.696 50.677 ;
  END
END ot_hbm_pc_refresh_cfg
END LIBRARY
